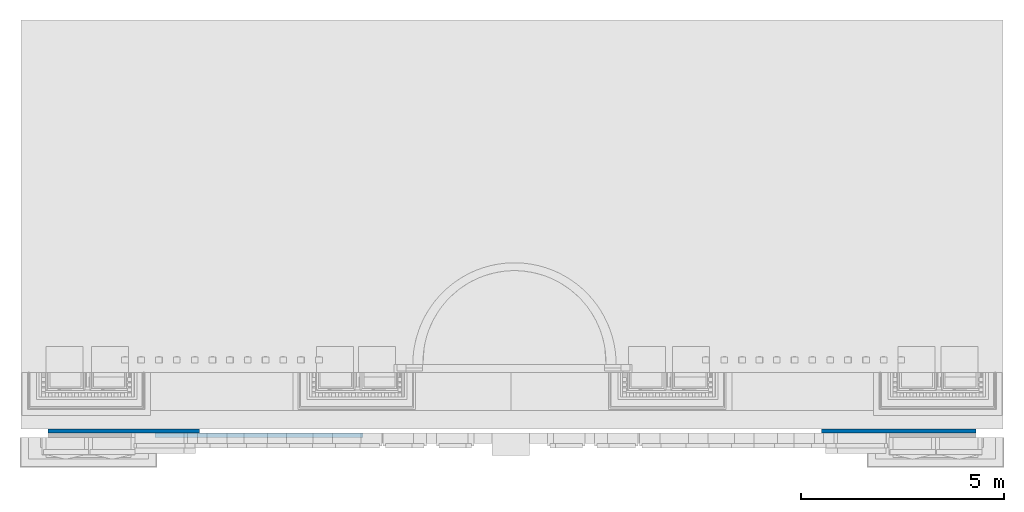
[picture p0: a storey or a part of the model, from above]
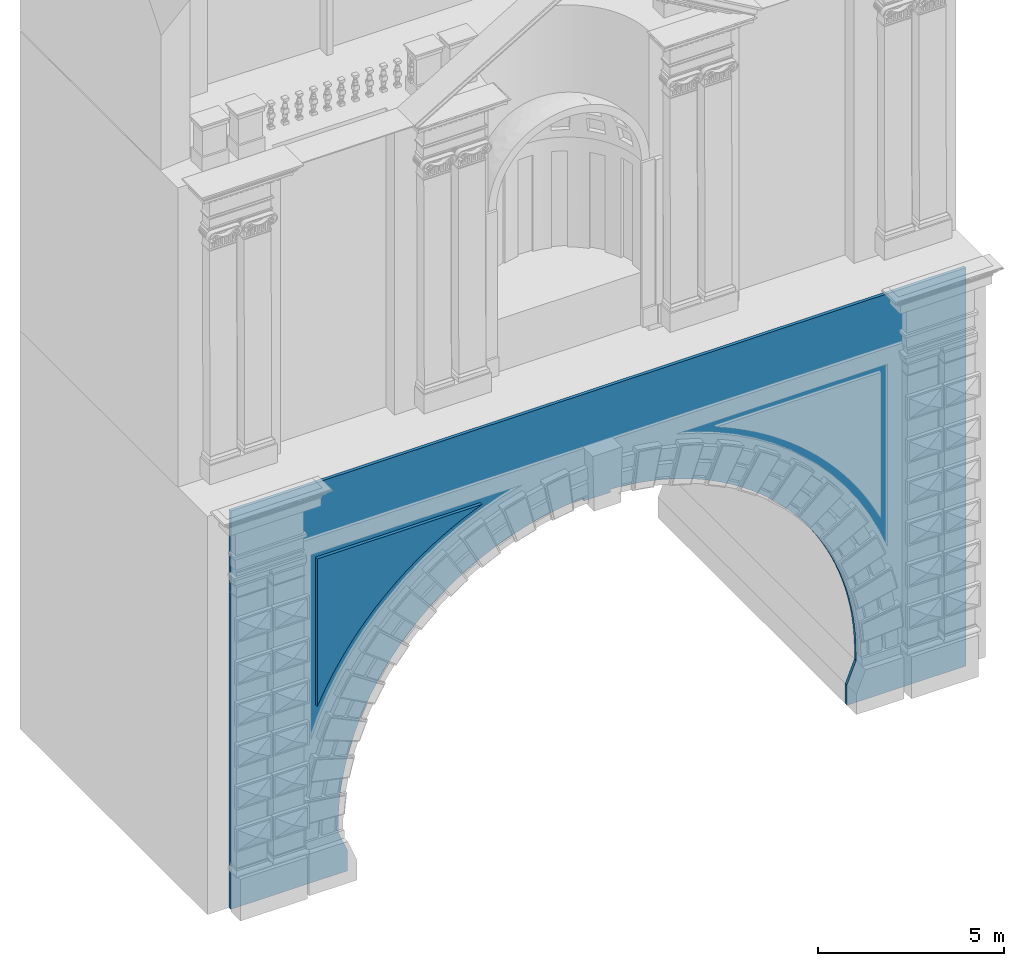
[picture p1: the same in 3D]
Properties of the parts of a building model (IFC2X3), part 1 of 2

# File
Description: ViewDefinition [CoordinationView_V2.0, QuantityTakeOffAddOnView]
File name: 0001
Time: 2019-05-15T13:14:59
Written by: The EXPRESS Data Manager Version 5.02.0100.07 : 28 Aug 2013
Made in: 20190108_1515(x64) - Exporter 19.2.1.1 - Alternate UI 19.2.1.1
Comment: STEP Physical File produced by: The EXPRESS Data Manager Version 5.02.0100.07 : 28 Aug 2013 * Module: EDMstepFileFactory/EDMstandAlone * Creation date: Wed May 15 13:14:59 2019 * Host: Angelo * Database: C:\Users\angel\AppData\Local\Temp\{2247383F-8AE9-40DE-8C0D-A3E6B9A9C0B3}\ifc * Database version: 5507 * Database creation date: Wed May 15 13:14:50 2019 * Schema: IFC2X3 * Model: DataRepository.ifc * Model creation date: Wed May 15 13:14:51 2019 * Header model: DataRepository.ifc_HeaderModel * Header model creation date: Wed May 15 13:14:51 2019 * EDMuser: sdai-user * EDMgroup: sdai-group * License ID and type: 5605 : Permanent license. Expiry date: * EDMstepFileFactory options: 020000

# IfcProject, 0001
LongName: Nome; Phase: Stato

# IfcSite, Default
RefLatitude: 41, 47, 59, 997253; RefLongitude: 12, 36, 0, 1373; RefElevation: 0 m
Altro - Categoria: Informazioni sul progetto; Data di consegna del progetto: Data; Indirizzo del progetto: Immettere l'indirizzo; Nome del cliente: Proprietario; Nome del progetto: Nome; Numero del progetto: 0001; Stato del progetto: Stato

# IfcBuilding
Pset_BuildingCommon - NumberOfStoreys: 3
Altro - Categoria: Informazioni sul progetto; Data di consegna del progetto: Data; Indirizzo del progetto: Immettere l'indirizzo; Nome del cliente: Proprietario; Nome del progetto: Nome; Numero del progetto: 0001; Stato del progetto: Stato

# IfcBuildingStorey (3)
Vincoli(Type) - Base quota altimetrica: Punto base progetto
Grafica(Type) - Colore: 0; Modello di linea: Centro; Simbolo: Estremità del livello - Cerchio: Estremità del livello - Cerchio; Simbolo a estremità 1 per default: no; Simbolo a estremità 2 per default: yes; Spessore di linea: 1
Dati identità(Type) - Nome del tipo: Estremità 8 mm
Altro(Type) - Categoria: Livelli; Nome famiglia: Livello
Altro - Categoria: Livelli; Famiglia: Livello: Estremità 8 mm; Famiglia e tipo: Livello: Estremità 8 mm; ID tipo: Livello: Estremità 8 mm; Tipo: Livello: Estremità 8 mm
Dati identità - Strutturale: no; Piano edificio: yes
Dimensioni - Altezza di calcolo: 0 m
Name | LongName = Nome | Elevation (m) = Quota altimetrica (m)
Livello 1 | Livello 1 | 0
Livello 2 | Livello 2 | 13.3668
Livello 3 | Livello 3 | 23.3294

# IfcBuildingElementProxy (414)
Pset_BuildingElementProxyCommon - Reference: Stratigrafia
Altro - Categoria: Stratigrafia
Dati - ESE_RI: 00
Dati identità - Mostra punti di manipolazione: no; Categoria originale: Modelli generici
Dimensioni - Esclusione: no; La forma è stata modificata: no
Fasi - Fase creata da originale: yes; Fase demolita da originale: yes; Fase di creazione: Fase 1
Name (Stratigrafia:...) | In | Material = Materiale | ESE_AR = ESE_RI_D = ESE_RI_M | Materiale in base a originale | Famiglia originale | Tipo originale | Volume (m3) | Livello di base
223069 | Livello 1 | Piperno | 01 | yes | Parasta_Piano terra | Parasta bugnata | 1.42777 | Livello: Livello 1
223070 | Livello 1 | Travertino | 01 | yes | Parasta_Piano terra | Parasta bugnata | 0.0227881 | Livello: Livello 1
223071 | Livello 1 | Travertino | 01 | yes | Parasta_Piano terra | Parasta bugnata | 2.51151 | Livello: Livello 1
223072 | Livello 1 | Piperno | 01 | yes | Parasta_Piano terra | Parasta bugnata | 0.101188 | Livello: Livello 1
223073 | Livello 1 | Piperno | 01 | yes | Parasta_Piano terra | Parasta bugnata | 0.101188 | Livello: Livello 1
223074 | Livello 1 | Piperno | 01 | yes | Parasta_Piano terra | Parasta bugnata | 0.101188 | Livello: Livello 1
223075 | Livello 1 | Piperno | 01 | yes | Parasta_Piano terra | Parasta bugnata | 0.101188 | Livello: Livello 1
223076 | Livello 1 | Piperno | 01 | yes | Parasta_Piano terra | Parasta bugnata | 0.101188 | Livello: Livello 1
223077 | Livello 1 | Piperno | 01 | yes | Parasta_Piano terra | Parasta bugnata | 0.101188 | Livello: Livello 1
223078 | Livello 1 | Travertino | 01 | yes | Parasta_Piano terra | Parasta bugnata | 0.0072461 | Livello: Livello 1
223079 | Livello 1 | Travertino | 01 | yes | Parasta_Piano terra | Parasta bugnata | 0.0966768 | Livello: Livello 1
223080 | Livello 1 | Travertino | 01 | yes | Parasta_Piano terra | Parasta bugnata | 0.02099 | Livello: Livello 1
223081 | Livello 1 | Travertino | 01 | yes | Parasta_Piano terra | Parasta bugnata | 0.0523646 | Livello: Livello 1
223082 | Livello 1 | Travertino | 01 | yes | Parasta_Piano terra | Parasta bugnata | 0.0608989 | Livello: Livello 1
223083 | Livello 1 | Travertino | 01 | yes | Parasta_Piano terra | Parasta bugnata | 0.0227881 | Livello: Livello 1
223084 | Livello 1 | Travertino | 01 | yes | Parasta_Piano terra | Parasta bugnata | 2.51151 | Livello: Livello 1
223085 | Livello 1 | Piperno | 01 | yes | Parasta_Piano terra | Parasta bugnata | 0.101188 | Livello: Livello 1
223086 | Livello 1 | Piperno | 01 | yes | Parasta_Piano terra | Parasta bugnata | 0.101188 | Livello: Livello 1
223087 | Livello 1 | Piperno | 01 | yes | Parasta_Piano terra | Parasta bugnata | 0.101188 | Livello: Livello 1
223088 | Livello 1 | Piperno | 01 | yes | Parasta_Piano terra | Parasta bugnata | 0.101188 | Livello: Livello 1
223089 | Livello 1 | Piperno | 01 | yes | Parasta_Piano terra | Parasta bugnata | 0.101188 | Livello: Livello 1
223090 | Livello 1 | Piperno | 01 | yes | Parasta_Piano terra | Parasta bugnata | 0.101188 | Livello: Livello 1
223091 | Livello 1 | Travertino | 01 | yes | Parasta_Piano terra | Parasta bugnata | 0.0072461 | Livello: Livello 1
223092 | Livello 1 | Travertino | 01 | yes | Parasta_Piano terra | Parasta bugnata | 0.0966768 | Livello: Livello 1
223093 | Livello 1 | Travertino | 01 | yes | Parasta_Piano terra | Parasta bugnata | 0.02099 | Livello: Livello 1
223094 | Livello 1 | Travertino | 01 | yes | Parasta_Piano terra | Parasta bugnata | 0.0523646 | Livello: Livello 1
223095 | Livello 1 | Travertino | 01 | yes | Parasta_Piano terra | Parasta bugnata | 0.0829303 | Livello: Livello 1
223096 | Livello 1 | Travertino | 01 | yes | Parasta_Piano terra | Parasta bugnata | 0.0317666 | Livello: Livello 1
223097 | Livello 1 | Piperno | 01 | yes | Parasta_Piano terra | Parasta bugnata | 0.207453 | Livello: Livello 1
223098 | Livello 1 | Piperno | 01 | yes | Parasta_Piano terra | Parasta bugnata | 0.0674188 | Livello: Livello 1
223099 | Livello 1 | Travertino | 01 | yes | Parasta_Piano terra | Parasta bugnata | 0.5069 | Livello: Livello 1
223100 | Livello 1 | Travertino | 01 | yes | Parasta_Piano terra | Parasta bugnata | 0.0573057 | Livello: Livello 1
223101 | Livello 1 | Travertino | 01 | yes | Parasta_Piano terra | Parasta bugnata | 0.026402 | Livello: Livello 1
223102 | Livello 1 | Travertino | 01 | yes | Parasta_Piano terra | Parasta bugnata | 0.0573057 | Livello: Livello 1
223103 | Livello 1 | Travertino | 01 | yes | Parasta_Piano terra | Parasta bugnata | 0.026402 | Livello: Livello 1
223104 | Livello 1 | Piperno | 01 | yes | Parasta_Piano terra | Parasta bugnata | 0.0268056 | Livello: Livello 1
223105 | Livello 1 | Piperno | 01 | yes | Parasta_Piano terra | Parasta bugnata | 0.0268056 | Livello: Livello 1
223106 | Livello 1 | Piperno | 01 | yes | Parasta_Piano terra | Parasta bugnata | 0.0268056 | Livello: Livello 1
223107 | Livello 1 | Piperno | 01 | yes | Parasta_Piano terra | Parasta bugnata | 0.0268056 | Livello: Livello 1
223108 | Livello 1 | Piperno | 01 | yes | Parasta_Piano terra | Parasta bugnata | 0.0268056 | Livello: Livello 1
223109 | Livello 1 | Piperno | 01 | yes | Parasta_Piano terra | Parasta bugnata | 0.0268056 | Livello: Livello 1
223110 | Livello 1 | Piperno | 01 | yes | Parasta_Piano terra | Parasta bugnata | 0.0268056 | Livello: Livello 1
223111 | Livello 1 | Piperno | 01 | yes | Parasta_Piano terra | Parasta bugnata | 0.0268056 | Livello: Livello 1
223112 | Livello 1 | Piperno | 01 | yes | Parasta_Piano terra | Parasta bugnata | 0.0268056 | Livello: Livello 1
223113 | Livello 1 | Piperno | 01 | yes | Parasta_Piano terra | Parasta bugnata | 0.0268056 | Livello: Livello 1
223114 | Livello 1 | Piperno | 01 | yes | Parasta_Piano terra | Parasta bugnata | 0.0268056 | Livello: Livello 1
223115 | Livello 1 | Piperno | 01 | yes | Parasta_Piano terra | Parasta bugnata | 0.0268056 | Livello: Livello 1
223116 | Livello 1 | Piperno | 01 | yes | Parasta_Piano terra | Parasta bugnata | 0.431277 | Livello: Livello 1
223117 | Livello 1 | Piperno | 01 | yes | Parasta_Piano terra | Parasta bugnata | 0.0748414 | Livello: Livello 1
223118 | Livello 1 | Piperno | 01 | yes | Parasta_Piano terra | Parasta bugnata | 0.132494 | Livello: Livello 1
223119 | Livello 1 | Piperno | 01 | yes | Parasta_Piano terra | Parasta bugnata | 0.369268 | Livello: Livello 1
223129 | Livello 1 | Travertino | 01 | yes | Arco Ingresso_Fronte Arcoleo | Arco ingresso bugnato | 3.44359 | Livello: Livello 1
223130 | Livello 1 | Piperno | 01 | yes | Arco Ingresso_Fronte Arcoleo | Arco ingresso bugnato | 0.303287 | Livello: Livello 1
223131 | Livello 1 | Piperno | 01 | yes | Arco Ingresso_Fronte Arcoleo | Arco ingresso bugnato | 0.083023 | Livello: Livello 1
223132 | Livello 1 | Piperno | 01 | yes | Arco Ingresso_Fronte Arcoleo | Arco ingresso bugnato | 0.303287 | Livello: Livello 1
223133 | Livello 1 | Piperno | 01 | yes | Arco Ingresso_Fronte Arcoleo | Arco ingresso bugnato | 0.083023 | Livello: Livello 1
223134 | Livello 1 | Piperno | 01 | yes | Arco Ingresso_Fronte Arcoleo | Arco ingresso bugnato | 0.303287 | Livello: Livello 1
223135 | Livello 1 | Piperno | 01 | yes | Arco Ingresso_Fronte Arcoleo | Arco ingresso bugnato | 0.083023 | Livello: Livello 1
223136 | Livello 1 | Piperno | 01 | yes | Arco Ingresso_Fronte Arcoleo | Arco ingresso bugnato | 0.303287 | Livello: Livello 1
223137 | Livello 1 | Piperno | 01 | yes | Arco Ingresso_Fronte Arcoleo | Arco ingresso bugnato | 0.083023 | Livello: Livello 1
223138 | Livello 1 | Piperno | 01 | yes | Arco Ingresso_Fronte Arcoleo | Arco ingresso bugnato | 0.303287 | Livello: Livello 1
223139 | Livello 1 | Piperno | 01 | yes | Arco Ingresso_Fronte Arcoleo | Arco ingresso bugnato | 0.083023 | Livello: Livello 1
223140 | Livello 1 | Piperno | 01 | yes | Arco Ingresso_Fronte Arcoleo | Arco ingresso bugnato | 0.303287 | Livello: Livello 1
223141 | Livello 1 | Piperno | 01 | yes | Arco Ingresso_Fronte Arcoleo | Arco ingresso bugnato | 0.083023 | Livello: Livello 1
223142 | Livello 1 | Piperno | 01 | yes | Arco Ingresso_Fronte Arcoleo | Arco ingresso bugnato | 0.303287 | Livello: Livello 1
223143 | Livello 1 | Piperno | 01 | yes | Arco Ingresso_Fronte Arcoleo | Arco ingresso bugnato | 0.083023 | Livello: Livello 1
223144 | Livello 1 | Piperno | 01 | yes | Arco Ingresso_Fronte Arcoleo | Arco ingresso bugnato | 0.303287 | Livello: Livello 1
223145 | Livello 1 | Piperno | 01 | yes | Arco Ingresso_Fronte Arcoleo | Arco ingresso bugnato | 0.083023 | Livello: Livello 1
223146 | Livello 1 | Piperno | 01 | yes | Arco Ingresso_Fronte Arcoleo | Arco ingresso bugnato | 0.303287 | Livello: Livello 1
223147 | Livello 1 | Piperno | 01 | yes | Arco Ingresso_Fronte Arcoleo | Arco ingresso bugnato | 0.083023 | Livello: Livello 1
223148 | Livello 1 | Piperno | 01 | yes | Arco Ingresso_Fronte Arcoleo | Arco ingresso bugnato | 0.303287 | Livello: Livello 1
223149 | Livello 1 | Piperno | 01 | yes | Arco Ingresso_Fronte Arcoleo | Arco ingresso bugnato | 0.083023 | Livello: Livello 1
223150 | Livello 1 | Piperno | 01 | yes | Arco Ingresso_Fronte Arcoleo | Arco ingresso bugnato | 0.866418 | Livello: Livello 1
223151 | Livello 1 | Piperno | 01 | yes | Arco Ingresso_Fronte Arcoleo | Arco ingresso bugnato | 0.303287 | Livello: Livello 1
223152 | Livello 1 | Piperno | 01 | yes | Arco Ingresso_Fronte Arcoleo | Arco ingresso bugnato | 0.083023 | Livello: Livello 1
223153 | Livello 1 | Piperno | 01 | yes | Arco Ingresso_Fronte Arcoleo | Arco ingresso bugnato | 0.303287 | Livello: Livello 1
223154 | Livello 1 | Piperno | 01 | yes | Arco Ingresso_Fronte Arcoleo | Arco ingresso bugnato | 0.083023 | Livello: Livello 1
223155 | Livello 1 | Piperno | 01 | yes | Arco Ingresso_Fronte Arcoleo | Arco ingresso bugnato | 0.303287 | Livello: Livello 1
223156 | Livello 1 | Piperno | 01 | yes | Arco Ingresso_Fronte Arcoleo | Arco ingresso bugnato | 0.083023 | Livello: Livello 1
223157 | Livello 1 | Piperno | 01 | yes | Arco Ingresso_Fronte Arcoleo | Arco ingresso bugnato | 0.303287 | Livello: Livello 1
223158 | Livello 1 | Piperno | 01 | yes | Arco Ingresso_Fronte Arcoleo | Arco ingresso bugnato | 0.083023 | Livello: Livello 1
223159 | Livello 1 | Piperno | 01 | yes | Arco Ingresso_Fronte Arcoleo | Arco ingresso bugnato | 0.303287 | Livello: Livello 1
223160 | Livello 1 | Piperno | 01 | yes | Arco Ingresso_Fronte Arcoleo | Arco ingresso bugnato | 0.083023 | Livello: Livello 1
223161 | Livello 1 | Piperno | 01 | yes | Arco Ingresso_Fronte Arcoleo | Arco ingresso bugnato | 0.303287 | Livello: Livello 1
223162 | Livello 1 | Piperno | 01 | yes | Arco Ingresso_Fronte Arcoleo | Arco ingresso bugnato | 0.083023 | Livello: Livello 1
223163 | Livello 1 | Piperno | 01 | yes | Arco Ingresso_Fronte Arcoleo | Arco ingresso bugnato | 0.303287 | Livello: Livello 1
223164 | Livello 1 | Piperno | 01 | yes | Arco Ingresso_Fronte Arcoleo | Arco ingresso bugnato | 0.083023 | Livello: Livello 1
223165 | Livello 1 | Piperno | 01 | yes | Arco Ingresso_Fronte Arcoleo | Arco ingresso bugnato | 0.303287 | Livello: Livello 1
223166 | Livello 1 | Piperno | 01 | yes | Arco Ingresso_Fronte Arcoleo | Arco ingresso bugnato | 0.083023 | Livello: Livello 1
223167 | Livello 1 | Piperno | 01 | yes | Arco Ingresso_Fronte Arcoleo | Arco ingresso bugnato | 0.303287 | Livello: Livello 1
223168 | Livello 1 | Piperno | 01 | yes | Arco Ingresso_Fronte Arcoleo | Arco ingresso bugnato | 0.083023 | Livello: Livello 1
223169 | Livello 1 | Piperno | 01 | yes | Arco Ingresso_Fronte Arcoleo | Arco ingresso bugnato | 0.303287 | Livello: Livello 1
223170 | Livello 1 | Piperno | 01 | yes | Arco Ingresso_Fronte Arcoleo | Arco ingresso bugnato | 0.083023 | Livello: Livello 1
223171 | Livello 1 | Travertino | 01 | yes | Arco Ingresso_Fronte Arcoleo | Arco ingresso bugnato | 3.44358 | Livello: Livello 1
223172 | Livello 1 | Piperno | 01 | yes | Arco Ingresso_Fronte Arcoleo | Arco ingresso bugnato | 0.963143 | Livello: Livello 1
223173 | Livello 1 | Travertino | 01 | yes | Arco Ingresso_Fronte Arcoleo | Arco ingresso bugnato | 0.102829 | Livello: Livello 1
223174 | Livello 1 | Piperno | 01 | yes | Arco Ingresso_Fronte Arcoleo | Arco ingresso bugnato | 0.963143 | Livello: Livello 1
223175 | Livello 1 | Travertino | 01 | yes | Arco Ingresso_Fronte Arcoleo | Arco ingresso bugnato | 0.102829 | Livello: Livello 1
223188 | Livello 1 | Piperno | 01 | yes | Parasta_Piano terra | Parasta bugnata | 1.42777 | Livello: Livello 1
223189 | Livello 1 | Travertino | 01 | yes | Parasta_Piano terra | Parasta bugnata | 0.0227881 | Livello: Livello 1
223190 | Livello 1 | Travertino | 01 | yes | Parasta_Piano terra | Parasta bugnata | 2.51151 | Livello: Livello 1
223191 | Livello 1 | Piperno | 01 | yes | Parasta_Piano terra | Parasta bugnata | 0.101188 | Livello: Livello 1
223192 | Livello 1 | Piperno | 01 | yes | Parasta_Piano terra | Parasta bugnata | 0.101188 | Livello: Livello 1
223193 | Livello 1 | Piperno | 01 | yes | Parasta_Piano terra | Parasta bugnata | 0.101188 | Livello: Livello 1
223194 | Livello 1 | Piperno | 01 | yes | Parasta_Piano terra | Parasta bugnata | 0.101188 | Livello: Livello 1
223195 | Livello 1 | Piperno | 01 | yes | Parasta_Piano terra | Parasta bugnata | 0.101188 | Livello: Livello 1
223196 | Livello 1 | Piperno | 01 | yes | Parasta_Piano terra | Parasta bugnata | 0.101188 | Livello: Livello 1
223197 | Livello 1 | Travertino | 01 | yes | Parasta_Piano terra | Parasta bugnata | 0.0072461 | Livello: Livello 1
223198 | Livello 1 | Travertino | 01 | yes | Parasta_Piano terra | Parasta bugnata | 0.0966768 | Livello: Livello 1
223199 | Livello 1 | Travertino | 01 | yes | Parasta_Piano terra | Parasta bugnata | 0.02099 | Livello: Livello 1
223200 | Livello 1 | Travertino | 01 | yes | Parasta_Piano terra | Parasta bugnata | 0.0523646 | Livello: Livello 1
223201 | Livello 1 | Travertino | 01 | yes | Parasta_Piano terra | Parasta bugnata | 0.0608989 | Livello: Livello 1
223202 | Livello 1 | Travertino | 01 | yes | Parasta_Piano terra | Parasta bugnata | 0.0227881 | Livello: Livello 1
223203 | Livello 1 | Travertino | 01 | yes | Parasta_Piano terra | Parasta bugnata | 2.51151 | Livello: Livello 1
223204 | Livello 1 | Piperno | 01 | yes | Parasta_Piano terra | Parasta bugnata | 0.101188 | Livello: Livello 1
223205 | Livello 1 | Piperno | 01 | yes | Parasta_Piano terra | Parasta bugnata | 0.101188 | Livello: Livello 1
223206 | Livello 1 | Piperno | 01 | yes | Parasta_Piano terra | Parasta bugnata | 0.101188 | Livello: Livello 1
223207 | Livello 1 | Piperno | 01 | yes | Parasta_Piano terra | Parasta bugnata | 0.101188 | Livello: Livello 1
223208 | Livello 1 | Piperno | 01 | yes | Parasta_Piano terra | Parasta bugnata | 0.101188 | Livello: Livello 1
223209 | Livello 1 | Piperno | 01 | yes | Parasta_Piano terra | Parasta bugnata | 0.101188 | Livello: Livello 1
223210 | Livello 1 | Travertino | 01 | yes | Parasta_Piano terra | Parasta bugnata | 0.0072461 | Livello: Livello 1
223211 | Livello 1 | Travertino | 01 | yes | Parasta_Piano terra | Parasta bugnata | 0.0966768 | Livello: Livello 1
223212 | Livello 1 | Travertino | 01 | yes | Parasta_Piano terra | Parasta bugnata | 0.02099 | Livello: Livello 1
223213 | Livello 1 | Travertino | 01 | yes | Parasta_Piano terra | Parasta bugnata | 0.0523646 | Livello: Livello 1
223214 | Livello 1 | Travertino | 01 | yes | Parasta_Piano terra | Parasta bugnata | 0.0829303 | Livello: Livello 1
223215 | Livello 1 | Travertino | 01 | yes | Parasta_Piano terra | Parasta bugnata | 0.0317666 | Livello: Livello 1
223216 | Livello 1 | Piperno | 01 | yes | Parasta_Piano terra | Parasta bugnata | 0.207453 | Livello: Livello 1
223217 | Livello 1 | Piperno | 01 | yes | Parasta_Piano terra | Parasta bugnata | 0.0674188 | Livello: Livello 1
223218 | Livello 1 | Travertino | 01 | yes | Parasta_Piano terra | Parasta bugnata | 0.5069 | Livello: Livello 1
223219 | Livello 1 | Travertino | 01 | yes | Parasta_Piano terra | Parasta bugnata | 0.0573057 | Livello: Livello 1
223220 | Livello 1 | Travertino | 01 | yes | Parasta_Piano terra | Parasta bugnata | 0.026402 | Livello: Livello 1
223221 | Livello 1 | Travertino | 01 | yes | Parasta_Piano terra | Parasta bugnata | 0.0573057 | Livello: Livello 1
223222 | Livello 1 | Travertino | 01 | yes | Parasta_Piano terra | Parasta bugnata | 0.026402 | Livello: Livello 1
223223 | Livello 1 | Piperno | 01 | yes | Parasta_Piano terra | Parasta bugnata | 0.0268056 | Livello: Livello 1
223224 | Livello 1 | Piperno | 01 | yes | Parasta_Piano terra | Parasta bugnata | 0.0268056 | Livello: Livello 1
223225 | Livello 1 | Piperno | 01 | yes | Parasta_Piano terra | Parasta bugnata | 0.0268056 | Livello: Livello 1
223226 | Livello 1 | Piperno | 01 | yes | Parasta_Piano terra | Parasta bugnata | 0.0268056 | Livello: Livello 1
223227 | Livello 1 | Piperno | 01 | yes | Parasta_Piano terra | Parasta bugnata | 0.0268056 | Livello: Livello 1
223228 | Livello 1 | Piperno | 01 | yes | Parasta_Piano terra | Parasta bugnata | 0.0268056 | Livello: Livello 1
223229 | Livello 1 | Piperno | 01 | yes | Parasta_Piano terra | Parasta bugnata | 0.0268056 | Livello: Livello 1
223230 | Livello 1 | Piperno | 01 | yes | Parasta_Piano terra | Parasta bugnata | 0.0268056 | Livello: Livello 1
223231 | Livello 1 | Piperno | 01 | yes | Parasta_Piano terra | Parasta bugnata | 0.0268056 | Livello: Livello 1
223232 | Livello 1 | Piperno | 01 | yes | Parasta_Piano terra | Parasta bugnata | 0.0268056 | Livello: Livello 1
223233 | Livello 1 | Piperno | 01 | yes | Parasta_Piano terra | Parasta bugnata | 0.0268056 | Livello: Livello 1
223234 | Livello 1 | Piperno | 01 | yes | Parasta_Piano terra | Parasta bugnata | 0.0268056 | Livello: Livello 1
223235 | Livello 1 | Piperno | 01 | yes | Parasta_Piano terra | Parasta bugnata | 0.431277 | Livello: Livello 1
223236 | Livello 1 | Piperno | 01 | yes | Parasta_Piano terra | Parasta bugnata | 0.0748414 | Livello: Livello 1
223237 | Livello 1 | Piperno | 01 | yes | Parasta_Piano terra | Parasta bugnata | 0.132494 | Livello: Livello 1
223238 | Livello 1 | Piperno | 01 | yes | Parasta_Piano terra | Parasta bugnata | 0.369268 | Livello: Livello 1
223248 | Livello 2 | Intonaco Liscio | 02 | yes | Nicchia Laterale | Nicchia Laterale | 5.30265 | Livello: Livello 2
223249 | Livello 2 | Piperno | 02 | yes | Nicchia Laterale | Nicchia Laterale | 0.838648 | Livello: Livello 2
223250 | Livello 2 | Travertino | 02 | yes | Nicchia Laterale | Nicchia Laterale | 0.519399 | Livello: Livello 2
223251 | Livello 2 | Travertino | 02 | no | Nicchia Laterale | Nicchia Laterale | 0.183577 | Livello: Livello 2
223252 | Livello 2 | Travertino | 02 | no | Nicchia Laterale | Nicchia Laterale | 0.0514958 | Livello: Livello 2
223253 | Livello 2 | Travertino | 02 | no | Nicchia Laterale | Nicchia Laterale | 0.065907 | Livello: Livello 2
223254 | Livello 2 | Travertino | 02 | no | Nicchia Laterale | Nicchia Laterale | 0.0524481 | Livello: Livello 2
223255 | Livello 2 | Travertino | 02 | no | Nicchia Laterale | Nicchia Laterale | 0.188709 | Livello: Livello 2
223256 | Livello 2 |  | 02 | yes | Nicchia Laterale | Nicchia Laterale | 0.978936 | Livello: Livello 2
223257 | Livello 2 | Travertino | 02 | yes | Nicchia Laterale | Nicchia Laterale | 0.102934 | Livello: Livello 2
223258 | Livello 2 | Travertino | 02 | yes | Nicchia Laterale | Nicchia Laterale | 0.190451 | Livello: Livello 2
223259 | Livello 2 | Travertino | 02 | yes | Nicchia Laterale | Nicchia Laterale | 0.170767 | Livello: Livello 2
223260 | Livello 2 | Travertino | 02 | yes | Nicchia Laterale | Nicchia Laterale | 0.102934 | Livello: Livello 2
223261 | Livello 2 | Travertino | 02 | yes | Nicchia Laterale | Nicchia Laterale | 0.190451 | Livello: Livello 2
223262 | Livello 2 | Travertino | 02 | yes | Nicchia Laterale | Nicchia Laterale | 0.170767 | Livello: Livello 2
223263 | Livello 2 | Intonaco Liscio | 02 | yes | Nicchia Laterale | Nicchia Laterale | 0.0603934 | Livello: Livello 2
223273 | Livello 1 | Travertino | 02 | yes | Nicchia centrale | Nicchia centrale | 3.82044 | Livello: Livello 1
223274 | Livello 1 | Travertino | 02 | yes | Nicchia centrale | Nicchia centrale | 0.158421 | Livello: Livello 1
223275 | Livello 1 | Travertino | 02 | yes | Nicchia centrale | Nicchia centrale | 0.159166 | Livello: Livello 1
223276 | Livello 1 | Travertino | 02 | yes | Nicchia centrale | Nicchia centrale | 0.158421 | Livello: Livello 1
223277 | Livello 1 | Travertino | 02 | yes | Nicchia centrale | Nicchia centrale | 0.159166 | Livello: Livello 1
223279 | Livello 1 | Travertino | 02 | yes | Nicchia centrale | Nicchia centrale | 6.73469 | Livello: Livello 1
223280 | Livello 1 | Intonaco Liscio | 02 | yes | Nicchia centrale | Nicchia centrale | 16.9 | Livello: Livello 1
223281 | Livello 1 | Travertino | 02 | yes | Nicchia centrale | Nicchia centrale | 0.0365358 | Livello: Livello 1
223282 | Livello 1 | Travertino | 02 | yes | Nicchia centrale | Nicchia centrale | 0.0352073 | Livello: Livello 1
223283 | Livello 1 | Travertino | 02 | yes | Nicchia centrale | Nicchia centrale | 0.0410155 | Livello: Livello 1
223284 | Livello 1 | Travertino | 02 | yes | Nicchia centrale | Nicchia centrale | 0.0258276 | Livello: Livello 1
223294 | Livello 2 | Intonaco Liscio | 02 | yes | Nicchia Laterale | Nicchia Laterale | 5.30265 | Livello: Livello 2
223295 | Livello 2 | Piperno | 02 | yes | Nicchia Laterale | Nicchia Laterale | 0.838648 | Livello: Livello 2
223296 | Livello 2 | Travertino | 02 | yes | Nicchia Laterale | Nicchia Laterale | 0.519399 | Livello: Livello 2
223297 | Livello 2 | Travertino | 02 | no | Nicchia Laterale | Nicchia Laterale | 0.183577 | Livello: Livello 2
223298 | Livello 2 | Travertino | 02 | no | Nicchia Laterale | Nicchia Laterale | 0.0514958 | Livello: Livello 2
223299 | Livello 2 | Travertino | 02 | no | Nicchia Laterale | Nicchia Laterale | 0.065907 | Livello: Livello 2
223300 | Livello 2 | Travertino | 02 | no | Nicchia Laterale | Nicchia Laterale | 0.0524481 | Livello: Livello 2
223301 | Livello 2 | Travertino | 02 | no | Nicchia Laterale | Nicchia Laterale | 0.188709 | Livello: Livello 2
223302 | Livello 2 |  | 02 | yes | Nicchia Laterale | Nicchia Laterale | 0.978936 | Livello: Livello 2
223303 | Livello 2 | Travertino | 02 | yes | Nicchia Laterale | Nicchia Laterale | 0.102934 | Livello: Livello 2
223304 | Livello 2 | Travertino | 02 | yes | Nicchia Laterale | Nicchia Laterale | 0.190451 | Livello: Livello 2
223305 | Livello 2 | Travertino | 02 | yes | Nicchia Laterale | Nicchia Laterale | 0.170767 | Livello: Livello 2
223306 | Livello 2 | Travertino | 02 | yes | Nicchia Laterale | Nicchia Laterale | 0.102934 | Livello: Livello 2
223307 | Livello 2 | Travertino | 02 | yes | Nicchia Laterale | Nicchia Laterale | 0.190451 | Livello: Livello 2
223308 | Livello 2 | Travertino | 02 | yes | Nicchia Laterale | Nicchia Laterale | 0.170767 | Livello: Livello 2
223309 | Livello 2 | Intonaco Liscio | 02 | yes | Nicchia Laterale | Nicchia Laterale | 0.0603934 | Livello: Livello 2
223386 | Livello 1 |  | 02 | yes | Parasta_Piano Primo 2 | Parasta Liscia_centrale | 0.00746349 | Livello: Livello 1
223387 | Livello 1 |  | 02 | yes | Parasta_Piano Primo 2 | Parasta Liscia_centrale | 0.0176679 | Livello: Livello 1
223388 | Livello 1 | Travertino | 02 | yes | Parasta_Piano Primo 2 | Parasta Liscia_centrale | 0.101618 | Livello: Livello 1
223391 | Livello 1 | Piperno | 02 | yes | Parasta_Piano Primo 2 | Parasta Liscia_centrale | 0.653767 | Livello: Livello 1
223392 | Livello 1 | Piperno | 02 | yes | Parasta_Piano Primo 2 | Parasta Liscia_centrale | 0.0556768 | Livello: Livello 1
223394 | Livello 1 | Piperno | 02 | yes | Parasta_Piano Primo 2 | Parasta Liscia_centrale | 2.15049 | Livello: Livello 1
223395 | Livello 1 |  | 02 | yes | Parasta_Piano Primo 2 | Parasta Liscia_centrale | 0.00746349 | Livello: Livello 1
223398 | Livello 1 |  | 02 | yes | Parasta_Piano Primo 2 | Parasta Liscia_centrale | 0.0176679 | Livello: Livello 1
223399 | Livello 1 | Travertino | 02 | yes | Parasta_Piano Primo 2 | Parasta Liscia_centrale | 0.101618 | Livello: Livello 1
223400 | Livello 1 | Travertino | 02 | yes | Parasta_Piano Primo 2 | Parasta Liscia_centrale | 0.066141 | Livello: Livello 1
223401 | Livello 1 | Travertino | 02 | yes | Parasta_Piano Primo 2 | Parasta Liscia_centrale | 0.108814 | Livello: Livello 1
223402 | Livello 1 | Travertino | 02 | yes | Parasta_Piano Primo 2 | Parasta Liscia_centrale | 0.0661334 | Livello: Livello 1
223403 | Livello 1 | Travertino | 02 | yes | Parasta_Piano Primo 2 | Parasta Liscia_centrale | 0.108807 | Livello: Livello 1
223448 | Livello 1 |  | 02 | yes | Parasta_Piano Primo 2 | Parasta Liscia_centrale | 0.00746349 | Livello: Livello 1
223449 | Livello 1 |  | 02 | yes | Parasta_Piano Primo 2 | Parasta Liscia_centrale | 0.0176679 | Livello: Livello 1
223450 | Livello 1 | Travertino | 02 | yes | Parasta_Piano Primo 2 | Parasta Liscia_centrale | 0.101618 | Livello: Livello 1
223453 | Livello 1 | Piperno | 02 | yes | Parasta_Piano Primo 2 | Parasta Liscia_centrale | 0.653767 | Livello: Livello 1
223454 | Livello 1 | Piperno | 02 | yes | Parasta_Piano Primo 2 | Parasta Liscia_centrale | 0.0556768 | Livello: Livello 1
223456 | Livello 1 | Piperno | 02 | yes | Parasta_Piano Primo 2 | Parasta Liscia_centrale | 2.15049 | Livello: Livello 1
223457 | Livello 1 |  | 02 | yes | Parasta_Piano Primo 2 | Parasta Liscia_centrale | 0.00746349 | Livello: Livello 1
223460 | Livello 1 |  | 02 | yes | Parasta_Piano Primo 2 | Parasta Liscia_centrale | 0.0176679 | Livello: Livello 1
223461 | Livello 1 | Travertino | 02 | yes | Parasta_Piano Primo 2 | Parasta Liscia_centrale | 0.101618 | Livello: Livello 1
223462 | Livello 1 | Travertino | 02 | yes | Parasta_Piano Primo 2 | Parasta Liscia_centrale | 0.066141 | Livello: Livello 1
223463 | Livello 1 | Travertino | 02 | yes | Parasta_Piano Primo 2 | Parasta Liscia_centrale | 0.108814 | Livello: Livello 1
223464 | Livello 1 | Travertino | 02 | yes | Parasta_Piano Primo 2 | Parasta Liscia_centrale | 0.0661334 | Livello: Livello 1
223465 | Livello 1 | Travertino | 02 | yes | Parasta_Piano Primo 2 | Parasta Liscia_centrale | 0.108807 | Livello: Livello 1
225919 | Livello 1 |  | 02 | yes | Parasta_Piano Primo 2 | Parasta Liscia_centrale | 0.00594878 | Livello: Livello 1
225920 | Livello 1 |  | 02 | yes | Parasta_Piano Primo 2 | Parasta Liscia_centrale | 0.00807559 | Livello: Livello 1
225921 | Livello 1 |  | 02 | yes | Parasta_Piano Primo 2 | Parasta Liscia_centrale | 0.0108989 | Livello: Livello 1
225922 | Livello 1 |  | 02 | yes | Parasta_Piano Primo 2 | Parasta Liscia_centrale | 0.0119519 | Livello: Livello 1
225923 | Livello 1 |  | 02 | yes | Parasta_Piano Primo 2 | Parasta Liscia_centrale | 0.0161303 | Livello: Livello 1
225924 | Livello 1 | Piperno | 02 | yes | Parasta_Piano Primo 2 | Parasta Liscia_centrale | 0.189326 | Livello: Livello 1
225925 | Livello 1 | Piperno | 02 | yes | Parasta_Piano Primo 2 | Parasta Liscia_centrale | 0.0100946 | Livello: Livello 1
225926 | Livello 1 | Piperno | 02 | yes | Parasta_Piano Primo 2 | Parasta Liscia_centrale | 0.0100946 | Livello: Livello 1
225927 | Livello 1 | Travertino | 02 | yes | Parasta_Piano Primo 2 | Parasta Liscia_centrale | 0.369222 | Livello: Livello 1
225928 | Livello 1 | Piperno | 02 | yes | Parasta_Piano Primo 2 | Parasta Liscia_centrale | 0.017309 | Livello: Livello 1
225929 | Livello 1 | Piperno | 02 | yes | Parasta_Piano Primo 2 | Parasta Liscia_centrale | 0.00282252 | Livello: Livello 1
225930 | Livello 1 | Piperno | 02 | yes | Parasta_Piano Primo 2 | Parasta Liscia_centrale | 0.0891707 | Livello: Livello 1
225931 | Livello 1 | Piperno | 02 | yes | Parasta_Piano Primo 2 | Parasta Liscia_centrale | 0.235123 | Livello: Livello 1
225933 | Livello 1 | Piperno | 02 | yes | Parasta_Piano Primo 2 | Parasta Liscia_centrale | 0.0898849 | Livello: Livello 1
225934 | Livello 1 | Piperno | 02 | yes | Parasta_Piano Primo 2 | Parasta Liscia_centrale | 0.0327858 | Livello: Livello 1
225935 | Livello 1 | Piperno | 02 | yes | Parasta_Piano Primo 2 | Parasta Liscia_centrale | 0.0944687 | Livello: Livello 1
225936 | Livello 1 | Piperno | 02 | yes | Parasta_Piano Primo 2 | Parasta Liscia_centrale | 0.00100709 | Livello: Livello 1
225937 | Livello 1 | Piperno | 02 | yes | Parasta_Piano Primo 2 | Parasta Liscia_centrale | 0.00100709 | Livello: Livello 1
225938 | Livello 1 | Piperno | 02 | yes | Parasta_Piano Primo 2 | Parasta Liscia_centrale | 0.00100709 | Livello: Livello 1
225939 | Livello 1 | Piperno | 02 | yes | Parasta_Piano Primo 2 | Parasta Liscia_centrale | 0.00100709 | Livello: Livello 1
225940 | Livello 1 | Piperno | 02 | yes | Parasta_Piano Primo 2 | Parasta Liscia_centrale | 0.00100709 | Livello: Livello 1
225941 | Livello 1 | Piperno | 02 | yes | Parasta_Piano Primo 2 | Parasta Liscia_centrale | 0.00100709 | Livello: Livello 1
225942 | Livello 1 | Piperno | 02 | yes | Parasta_Piano Primo 2 | Parasta Liscia_centrale | 0.00100709 | Livello: Livello 1
225943 | Livello 1 | Piperno | 02 | yes | Parasta_Piano Primo 2 | Parasta Liscia_centrale | 0.00100709 | Livello: Livello 1
225944 | Livello 1 | Piperno | 02 | yes | Parasta_Piano Primo 2 | Parasta Liscia_centrale | 0.00100709 | Livello: Livello 1
225945 | Livello 1 | Piperno | 02 | yes | Parasta_Piano Primo 2 | Parasta Liscia_centrale | 0.00100709 | Livello: Livello 1
225946 | Livello 1 | Piperno | 02 | yes | Parasta_Piano Primo 2 | Parasta Liscia_centrale | 0.00100709 | Livello: Livello 1
225947 | Livello 1 | Piperno | 02 | yes | Parasta_Piano Primo 2 | Parasta Liscia_centrale | 0.00100709 | Livello: Livello 1
225948 | Livello 1 | Piperno | 02 | yes | Parasta_Piano Primo 2 | Parasta Liscia_centrale | 0.00100709 | Livello: Livello 1
225949 | Livello 1 | Piperno | 02 | yes | Parasta_Piano Primo 2 | Parasta Liscia_centrale | 0.00100709 | Livello: Livello 1
225950 | Livello 1 | Piperno | 02 | yes | Parasta_Piano Primo 2 | Parasta Liscia_centrale | 0.00100709 | Livello: Livello 1
225951 | Livello 1 | Piperno | 02 | yes | Parasta_Piano Primo 2 | Parasta Liscia_centrale | 0.00100709 | Livello: Livello 1
225952 | Livello 1 | Piperno | 02 | yes | Parasta_Piano Primo 2 | Parasta Liscia_centrale | 0.00100709 | Livello: Livello 1
225953 | Livello 1 | Piperno | 02 | yes | Parasta_Piano Primo 2 | Parasta Liscia_centrale | 0.00100709 | Livello: Livello 1
225954 | Livello 1 | Piperno | 02 | yes | Parasta_Piano Primo 2 | Parasta Liscia_centrale | 0.00100709 | Livello: Livello 1
225955 | Livello 1 | Piperno | 02 | yes | Parasta_Piano Primo 2 | Parasta Liscia_centrale | 0.00100709 | Livello: Livello 1
225956 | Livello 1 | Piperno | 02 | yes | Parasta_Piano Primo 2 | Parasta Liscia_centrale | 0.0556768 | Livello: Livello 1
225957 | Livello 1 | Piperno | 02 | yes | Parasta_Piano Primo 2 | Parasta Liscia_centrale | 2.15049 | Livello: Livello 1
225958 | Livello 1 |  | 02 | yes | Parasta_Piano Primo 2 | Parasta Liscia_centrale | 0.00594878 | Livello: Livello 1
225959 | Livello 1 |  | 02 | yes | Parasta_Piano Primo 2 | Parasta Liscia_centrale | 0.00594878 | Livello: Livello 1
225960 | Livello 1 |  | 02 | yes | Parasta_Piano Primo 2 | Parasta Liscia_centrale | 0.00807559 | Livello: Livello 1
225961 | Livello 1 |  | 02 | yes | Parasta_Piano Primo 2 | Parasta Liscia_centrale | 0.0108989 | Livello: Livello 1
225962 | Livello 1 |  | 02 | yes | Parasta_Piano Primo 2 | Parasta Liscia_centrale | 0.0119519 | Livello: Livello 1
225963 | Livello 1 |  | 02 | yes | Parasta_Piano Primo 2 | Parasta Liscia_centrale | 0.0161303 | Livello: Livello 1
225964 | Livello 1 | Piperno | 02 | yes | Parasta_Piano Primo 2 | Parasta Liscia_centrale | 0.189326 | Livello: Livello 1
225965 | Livello 1 | Piperno | 02 | yes | Parasta_Piano Primo 2 | Parasta Liscia_centrale | 0.0100946 | Livello: Livello 1
225966 | Livello 1 | Piperno | 02 | yes | Parasta_Piano Primo 2 | Parasta Liscia_centrale | 0.0100946 | Livello: Livello 1
225967 | Livello 1 | Travertino | 02 | yes | Parasta_Piano Primo 2 | Parasta Liscia_centrale | 0.369222 | Livello: Livello 1
225968 | Livello 1 | Piperno | 02 | yes | Parasta_Piano Primo 2 | Parasta Liscia_centrale | 0.017309 | Livello: Livello 1
225969 | Livello 1 | Piperno | 02 | yes | Parasta_Piano Primo 2 | Parasta Liscia_centrale | 0.00282252 | Livello: Livello 1
225970 | Livello 1 | Piperno | 02 | yes | Parasta_Piano Primo 2 | Parasta Liscia_centrale | 0.0891707 | Livello: Livello 1
225971 | Livello 1 | Piperno | 02 | yes | Parasta_Piano Primo 2 | Parasta Liscia_centrale | 0.235123 | Livello: Livello 1
225973 | Livello 1 | Piperno | 02 | yes | Parasta_Piano Primo 2 | Parasta Liscia_centrale | 0.0898849 | Livello: Livello 1
225974 | Livello 1 | Piperno | 02 | yes | Parasta_Piano Primo 2 | Parasta Liscia_centrale | 0.0327858 | Livello: Livello 1
225975 | Livello 1 | Piperno | 02 | yes | Parasta_Piano Primo 2 | Parasta Liscia_centrale | 0.0944687 | Livello: Livello 1
225976 | Livello 1 | Piperno | 02 | yes | Parasta_Piano Primo 2 | Parasta Liscia_centrale | 0.00100709 | Livello: Livello 1
225977 | Livello 1 | Piperno | 02 | yes | Parasta_Piano Primo 2 | Parasta Liscia_centrale | 0.00100709 | Livello: Livello 1
225978 | Livello 1 | Piperno | 02 | yes | Parasta_Piano Primo 2 | Parasta Liscia_centrale | 0.00100709 | Livello: Livello 1
225979 | Livello 1 | Piperno | 02 | yes | Parasta_Piano Primo 2 | Parasta Liscia_centrale | 0.00100709 | Livello: Livello 1
225980 | Livello 1 | Piperno | 02 | yes | Parasta_Piano Primo 2 | Parasta Liscia_centrale | 0.00100709 | Livello: Livello 1
225981 | Livello 1 | Piperno | 02 | yes | Parasta_Piano Primo 2 | Parasta Liscia_centrale | 0.00100709 | Livello: Livello 1
225982 | Livello 1 | Piperno | 02 | yes | Parasta_Piano Primo 2 | Parasta Liscia_centrale | 0.00100709 | Livello: Livello 1
225983 | Livello 1 | Piperno | 02 | yes | Parasta_Piano Primo 2 | Parasta Liscia_centrale | 0.00100709 | Livello: Livello 1
225984 | Livello 1 | Piperno | 02 | yes | Parasta_Piano Primo 2 | Parasta Liscia_centrale | 0.00100709 | Livello: Livello 1
225985 | Livello 1 | Piperno | 02 | yes | Parasta_Piano Primo 2 | Parasta Liscia_centrale | 0.00100709 | Livello: Livello 1
225986 | Livello 1 | Piperno | 02 | yes | Parasta_Piano Primo 2 | Parasta Liscia_centrale | 0.00100709 | Livello: Livello 1
225987 | Livello 1 | Piperno | 02 | yes | Parasta_Piano Primo 2 | Parasta Liscia_centrale | 0.00100709 | Livello: Livello 1
225988 | Livello 1 | Piperno | 02 | yes | Parasta_Piano Primo 2 | Parasta Liscia_centrale | 0.00100709 | Livello: Livello 1
225989 | Livello 1 | Piperno | 02 | yes | Parasta_Piano Primo 2 | Parasta Liscia_centrale | 0.00100709 | Livello: Livello 1
225990 | Livello 1 | Piperno | 02 | yes | Parasta_Piano Primo 2 | Parasta Liscia_centrale | 0.00100709 | Livello: Livello 1
225991 | Livello 1 | Piperno | 02 | yes | Parasta_Piano Primo 2 | Parasta Liscia_centrale | 0.00100709 | Livello: Livello 1
225992 | Livello 1 | Piperno | 02 | yes | Parasta_Piano Primo 2 | Parasta Liscia_centrale | 0.00100709 | Livello: Livello 1
225993 | Livello 1 | Piperno | 02 | yes | Parasta_Piano Primo 2 | Parasta Liscia_centrale | 0.00100709 | Livello: Livello 1
225994 | Livello 1 | Piperno | 02 | yes | Parasta_Piano Primo 2 | Parasta Liscia_centrale | 0.00100709 | Livello: Livello 1
225995 | Livello 1 | Piperno | 02 | yes | Parasta_Piano Primo 2 | Parasta Liscia_centrale | 0.00100709 | Livello: Livello 1
225996 | Livello 1 | Piperno | 02 | yes | Parasta_Piano Primo 2 | Parasta Liscia_centrale | 0.0556768 | Livello: Livello 1
225997 | Livello 1 | Piperno | 02 | yes | Parasta_Piano Primo 2 | Parasta Liscia_centrale | 2.15049 | Livello: Livello 1
225998 | Livello 1 |  | 02 | yes | Parasta_Piano Primo 2 | Parasta Liscia_centrale | 0.00594878 | Livello: Livello 1
229239 | Livello 1 | Piperno | 02 | yes | Parasta_Piano Primo 2 | Parasta Liscia_centrale | 0.0423479 | Livello: Livello 1
229240 | Livello 1 | Piperno | 02 | yes | Parasta_Piano Primo 2 | Parasta Liscia_centrale | 0.00427694 | Livello: Livello 1
229241 | Livello 1 | Piperno | 02 | yes | Parasta_Piano Primo 2 | Parasta Liscia_centrale | 0.0423479 | Livello: Livello 1
229242 | Livello 1 | Piperno | 02 | yes | Parasta_Piano Primo 2 | Parasta Liscia_centrale | 0.00427694 | Livello: Livello 1
235061 | Livello 1 | Piperno | 02 | yes | Parasta_ Piano Primo | Parasta Liscia_laterale | 0.173421 | Livello: Livello 1
235062 | Livello 1 | Piperno | 02 | yes | Parasta_ Piano Primo | Parasta Liscia_laterale | 0.0625004 | Livello: Livello 1
235063 | Livello 1 | Piperno | 02 | yes | Parasta_ Piano Primo | Parasta Liscia_laterale | 0.002813 | Livello: Livello 1
235064 | Livello 1 |  | 02 | yes | Parasta_ Piano Primo | Parasta Liscia_laterale | 0.00746349 | Livello: Livello 1
235065 | Livello 1 |  | 02 | yes | Parasta_ Piano Primo | Parasta Liscia_laterale | 0.0176679 | Livello: Livello 1
235066 | Livello 1 | Travertino | 02 | yes | Parasta_ Piano Primo | Parasta Liscia_laterale | 0.101618 | Livello: Livello 1
235067 | Livello 1 | Piperno | 02 | yes | Parasta_ Piano Primo | Parasta Liscia_laterale | 0.653767 | Livello: Livello 1
235068 | Livello 1 | Piperno | 02 | yes | Parasta_ Piano Primo | Parasta Liscia_laterale | 0.0556768 | Livello: Livello 1
235069 | Livello 1 | Piperno | 02 | yes | Parasta_ Piano Primo | Parasta Liscia_laterale | 2.15049 | Livello: Livello 1
235070 | Livello 1 |  | 02 | yes | Parasta_ Piano Primo | Parasta Liscia_laterale | 0.00746349 | Livello: Livello 1
235071 | Livello 1 |  | 02 | yes | Parasta_ Piano Primo | Parasta Liscia_laterale | 0.0176679 | Livello: Livello 1
235072 | Livello 1 | Travertino | 02 | yes | Parasta_ Piano Primo | Parasta Liscia_laterale | 0.101618 | Livello: Livello 1
235073 | Livello 1 | Travertino | 02 | yes | Parasta_ Piano Primo | Parasta Liscia_laterale | 0.066141 | Livello: Livello 1
235074 | Livello 1 | Travertino | 02 | yes | Parasta_ Piano Primo | Parasta Liscia_laterale | 0.108814 | Livello: Livello 1
235075 | Livello 1 | Travertino | 02 | yes | Parasta_ Piano Primo | Parasta Liscia_laterale | 0.0661334 | Livello: Livello 1
235076 | Livello 1 | Travertino | 02 | yes | Parasta_ Piano Primo | Parasta Liscia_laterale | 0.108807 | Livello: Livello 1
235077 | Livello 1 |  | 02 | yes | Parasta_ Piano Primo | Parasta Liscia_laterale | 0.00594878 | Livello: Livello 1
235078 | Livello 1 |  | 02 | yes | Parasta_ Piano Primo | Parasta Liscia_laterale | 0.00807559 | Livello: Livello 1
235079 | Livello 1 |  | 02 | yes | Parasta_ Piano Primo | Parasta Liscia_laterale | 0.0108989 | Livello: Livello 1
235080 | Livello 1 |  | 02 | yes | Parasta_ Piano Primo | Parasta Liscia_laterale | 0.0119519 | Livello: Livello 1
235081 | Livello 1 |  | 02 | yes | Parasta_ Piano Primo | Parasta Liscia_laterale | 0.0161303 | Livello: Livello 1
235082 | Livello 1 | Piperno | 02 | yes | Parasta_ Piano Primo | Parasta Liscia_laterale | 0.189326 | Livello: Livello 1
235083 | Livello 1 | Piperno | 02 | yes | Parasta_ Piano Primo | Parasta Liscia_laterale | 0.0100946 | Livello: Livello 1
235084 | Livello 1 | Piperno | 02 | yes | Parasta_ Piano Primo | Parasta Liscia_laterale | 0.0100946 | Livello: Livello 1
235085 | Livello 1 | Travertino | 02 | yes | Parasta_ Piano Primo | Parasta Liscia_laterale | 0.369222 | Livello: Livello 1
235086 | Livello 1 | Piperno | 02 | yes | Parasta_ Piano Primo | Parasta Liscia_laterale | 0.017309 | Livello: Livello 1
235087 | Livello 1 | Piperno | 02 | yes | Parasta_ Piano Primo | Parasta Liscia_laterale | 0.00282252 | Livello: Livello 1
235088 | Livello 1 | Piperno | 02 | yes | Parasta_ Piano Primo | Parasta Liscia_laterale | 0.0891707 | Livello: Livello 1
235089 | Livello 1 | Piperno | 02 | yes | Parasta_ Piano Primo | Parasta Liscia_laterale | 0.235123 | Livello: Livello 1
235090 | Livello 1 | Piperno | 02 | yes | Parasta_ Piano Primo | Parasta Liscia_laterale | 0.0898849 | Livello: Livello 1
235091 | Livello 1 | Piperno | 02 | yes | Parasta_ Piano Primo | Parasta Liscia_laterale | 0.0327858 | Livello: Livello 1
235092 | Livello 1 | Piperno | 02 | yes | Parasta_ Piano Primo | Parasta Liscia_laterale | 0.0944687 | Livello: Livello 1
235093 | Livello 1 | Piperno | 02 | yes | Parasta_ Piano Primo | Parasta Liscia_laterale | 0.00100709 | Livello: Livello 1
235094 | Livello 1 | Piperno | 02 | yes | Parasta_ Piano Primo | Parasta Liscia_laterale | 0.00100709 | Livello: Livello 1
235095 | Livello 1 | Piperno | 02 | yes | Parasta_ Piano Primo | Parasta Liscia_laterale | 0.00100709 | Livello: Livello 1
235096 | Livello 1 | Piperno | 02 | yes | Parasta_ Piano Primo | Parasta Liscia_laterale | 0.00100709 | Livello: Livello 1
235097 | Livello 1 | Piperno | 02 | yes | Parasta_ Piano Primo | Parasta Liscia_laterale | 0.00100709 | Livello: Livello 1
235098 | Livello 1 | Piperno | 02 | yes | Parasta_ Piano Primo | Parasta Liscia_laterale | 0.00100709 | Livello: Livello 1
235099 | Livello 1 | Piperno | 02 | yes | Parasta_ Piano Primo | Parasta Liscia_laterale | 0.00100709 | Livello: Livello 1
235100 | Livello 1 | Piperno | 02 | yes | Parasta_ Piano Primo | Parasta Liscia_laterale | 0.00100709 | Livello: Livello 1
235101 | Livello 1 | Piperno | 02 | yes | Parasta_ Piano Primo | Parasta Liscia_laterale | 0.00100709 | Livello: Livello 1
235102 | Livello 1 | Piperno | 02 | yes | Parasta_ Piano Primo | Parasta Liscia_laterale | 0.00100709 | Livello: Livello 1
235103 | Livello 1 | Piperno | 02 | yes | Parasta_ Piano Primo | Parasta Liscia_laterale | 0.00100709 | Livello: Livello 1
235104 | Livello 1 | Piperno | 02 | yes | Parasta_ Piano Primo | Parasta Liscia_laterale | 0.00100709 | Livello: Livello 1
235105 | Livello 1 | Piperno | 02 | yes | Parasta_ Piano Primo | Parasta Liscia_laterale | 0.00100709 | Livello: Livello 1
235106 | Livello 1 | Piperno | 02 | yes | Parasta_ Piano Primo | Parasta Liscia_laterale | 0.00100709 | Livello: Livello 1
235107 | Livello 1 | Piperno | 02 | yes | Parasta_ Piano Primo | Parasta Liscia_laterale | 0.00100709 | Livello: Livello 1
235108 | Livello 1 | Piperno | 02 | yes | Parasta_ Piano Primo | Parasta Liscia_laterale | 0.00100709 | Livello: Livello 1
235109 | Livello 1 | Piperno | 02 | yes | Parasta_ Piano Primo | Parasta Liscia_laterale | 0.00100709 | Livello: Livello 1
235110 | Livello 1 | Piperno | 02 | yes | Parasta_ Piano Primo | Parasta Liscia_laterale | 0.00100709 | Livello: Livello 1
235111 | Livello 1 | Piperno | 02 | yes | Parasta_ Piano Primo | Parasta Liscia_laterale | 0.00100709 | Livello: Livello 1
235112 | Livello 1 | Piperno | 02 | yes | Parasta_ Piano Primo | Parasta Liscia_laterale | 0.00100709 | Livello: Livello 1
235113 | Livello 1 | Piperno | 02 | yes | Parasta_ Piano Primo | Parasta Liscia_laterale | 0.0556768 | Livello: Livello 1
235114 | Livello 1 | Piperno | 02 | yes | Parasta_ Piano Primo | Parasta Liscia_laterale | 2.15049 | Livello: Livello 1
235115 | Livello 1 |  | 02 | yes | Parasta_ Piano Primo | Parasta Liscia_laterale | 0.00594878 | Livello: Livello 1
235116 | Livello 1 | Piperno | 02 | yes | Parasta_ Piano Primo | Parasta Liscia_laterale | 0.0423479 | Livello: Livello 1
235117 | Livello 1 | Piperno | 02 | yes | Parasta_ Piano Primo | Parasta Liscia_laterale | 0.00427694 | Livello: Livello 1
235141 | Livello 1 | Piperno | 02 | yes | Parasta_ Piano Primo | Parasta Liscia_laterale | 0.173421 | Livello: Livello 1
235142 | Livello 1 | Piperno | 02 | yes | Parasta_ Piano Primo | Parasta Liscia_laterale | 0.0625004 | Livello: Livello 1
235143 | Livello 1 | Piperno | 02 | yes | Parasta_ Piano Primo | Parasta Liscia_laterale | 0.002813 | Livello: Livello 1
235144 | Livello 1 |  | 02 | yes | Parasta_ Piano Primo | Parasta Liscia_laterale | 0.00746349 | Livello: Livello 1
235145 | Livello 1 |  | 02 | yes | Parasta_ Piano Primo | Parasta Liscia_laterale | 0.0176679 | Livello: Livello 1
235146 | Livello 1 | Travertino | 02 | yes | Parasta_ Piano Primo | Parasta Liscia_laterale | 0.101618 | Livello: Livello 1
235147 | Livello 1 | Piperno | 02 | yes | Parasta_ Piano Primo | Parasta Liscia_laterale | 0.653767 | Livello: Livello 1
235148 | Livello 1 | Piperno | 02 | yes | Parasta_ Piano Primo | Parasta Liscia_laterale | 0.0556768 | Livello: Livello 1
235149 | Livello 1 | Piperno | 02 | yes | Parasta_ Piano Primo | Parasta Liscia_laterale | 2.15049 | Livello: Livello 1
235150 | Livello 1 |  | 02 | yes | Parasta_ Piano Primo | Parasta Liscia_laterale | 0.00746349 | Livello: Livello 1
235151 | Livello 1 |  | 02 | yes | Parasta_ Piano Primo | Parasta Liscia_laterale | 0.0176679 | Livello: Livello 1
235152 | Livello 1 | Travertino | 02 | yes | Parasta_ Piano Primo | Parasta Liscia_laterale | 0.101618 | Livello: Livello 1
235153 | Livello 1 | Travertino | 02 | yes | Parasta_ Piano Primo | Parasta Liscia_laterale | 0.066141 | Livello: Livello 1
235154 | Livello 1 | Travertino | 02 | yes | Parasta_ Piano Primo | Parasta Liscia_laterale | 0.108814 | Livello: Livello 1
235155 | Livello 1 | Travertino | 02 | yes | Parasta_ Piano Primo | Parasta Liscia_laterale | 0.0661334 | Livello: Livello 1
235156 | Livello 1 | Travertino | 02 | yes | Parasta_ Piano Primo | Parasta Liscia_laterale | 0.108807 | Livello: Livello 1
235157 | Livello 1 |  | 02 | yes | Parasta_ Piano Primo | Parasta Liscia_laterale | 0.00594878 | Livello: Livello 1
235158 | Livello 1 |  | 02 | yes | Parasta_ Piano Primo | Parasta Liscia_laterale | 0.00807559 | Livello: Livello 1
235159 | Livello 1 |  | 02 | yes | Parasta_ Piano Primo | Parasta Liscia_laterale | 0.0108989 | Livello: Livello 1
235160 | Livello 1 |  | 02 | yes | Parasta_ Piano Primo | Parasta Liscia_laterale | 0.0119519 | Livello: Livello 1
235161 | Livello 1 |  | 02 | yes | Parasta_ Piano Primo | Parasta Liscia_laterale | 0.0161303 | Livello: Livello 1
235162 | Livello 1 | Piperno | 02 | yes | Parasta_ Piano Primo | Parasta Liscia_laterale | 0.189326 | Livello: Livello 1
235163 | Livello 1 | Piperno | 02 | yes | Parasta_ Piano Primo | Parasta Liscia_laterale | 0.0100946 | Livello: Livello 1
235164 | Livello 1 | Piperno | 02 | yes | Parasta_ Piano Primo | Parasta Liscia_laterale | 0.0100946 | Livello: Livello 1
235165 | Livello 1 | Travertino | 02 | yes | Parasta_ Piano Primo | Parasta Liscia_laterale | 0.369222 | Livello: Livello 1
235166 | Livello 1 | Piperno | 02 | yes | Parasta_ Piano Primo | Parasta Liscia_laterale | 0.017309 | Livello: Livello 1
235167 | Livello 1 | Piperno | 02 | yes | Parasta_ Piano Primo | Parasta Liscia_laterale | 0.00282252 | Livello: Livello 1
235168 | Livello 1 | Piperno | 02 | yes | Parasta_ Piano Primo | Parasta Liscia_laterale | 0.0891707 | Livello: Livello 1
235169 | Livello 1 | Piperno | 02 | yes | Parasta_ Piano Primo | Parasta Liscia_laterale | 0.235123 | Livello: Livello 1
235170 | Livello 1 | Piperno | 02 | yes | Parasta_ Piano Primo | Parasta Liscia_laterale | 0.0898849 | Livello: Livello 1
235171 | Livello 1 | Piperno | 02 | yes | Parasta_ Piano Primo | Parasta Liscia_laterale | 0.0327858 | Livello: Livello 1
235172 | Livello 1 | Piperno | 02 | yes | Parasta_ Piano Primo | Parasta Liscia_laterale | 0.0944687 | Livello: Livello 1
235173 | Livello 1 | Piperno | 02 | yes | Parasta_ Piano Primo | Parasta Liscia_laterale | 0.00100709 | Livello: Livello 1
235174 | Livello 1 | Piperno | 02 | yes | Parasta_ Piano Primo | Parasta Liscia_laterale | 0.00100709 | Livello: Livello 1
235175 | Livello 1 | Piperno | 02 | yes | Parasta_ Piano Primo | Parasta Liscia_laterale | 0.00100709 | Livello: Livello 1
235176 | Livello 1 | Piperno | 02 | yes | Parasta_ Piano Primo | Parasta Liscia_laterale | 0.00100709 | Livello: Livello 1
235177 | Livello 1 | Piperno | 02 | yes | Parasta_ Piano Primo | Parasta Liscia_laterale | 0.00100709 | Livello: Livello 1
235178 | Livello 1 | Piperno | 02 | yes | Parasta_ Piano Primo | Parasta Liscia_laterale | 0.00100709 | Livello: Livello 1
235179 | Livello 1 | Piperno | 02 | yes | Parasta_ Piano Primo | Parasta Liscia_laterale | 0.00100709 | Livello: Livello 1
235180 | Livello 1 | Piperno | 02 | yes | Parasta_ Piano Primo | Parasta Liscia_laterale | 0.00100709 | Livello: Livello 1
235181 | Livello 1 | Piperno | 02 | yes | Parasta_ Piano Primo | Parasta Liscia_laterale | 0.00100709 | Livello: Livello 1
235182 | Livello 1 | Piperno | 02 | yes | Parasta_ Piano Primo | Parasta Liscia_laterale | 0.00100709 | Livello: Livello 1
235183 | Livello 1 | Piperno | 02 | yes | Parasta_ Piano Primo | Parasta Liscia_laterale | 0.00100709 | Livello: Livello 1
235184 | Livello 1 | Piperno | 02 | yes | Parasta_ Piano Primo | Parasta Liscia_laterale | 0.00100709 | Livello: Livello 1
235185 | Livello 1 | Piperno | 02 | yes | Parasta_ Piano Primo | Parasta Liscia_laterale | 0.00100709 | Livello: Livello 1
235186 | Livello 1 | Piperno | 02 | yes | Parasta_ Piano Primo | Parasta Liscia_laterale | 0.00100709 | Livello: Livello 1
235187 | Livello 1 | Piperno | 02 | yes | Parasta_ Piano Primo | Parasta Liscia_laterale | 0.00100709 | Livello: Livello 1
235188 | Livello 1 | Piperno | 02 | yes | Parasta_ Piano Primo | Parasta Liscia_laterale | 0.00100709 | Livello: Livello 1
235189 | Livello 1 | Piperno | 02 | yes | Parasta_ Piano Primo | Parasta Liscia_laterale | 0.00100709 | Livello: Livello 1
235190 | Livello 1 | Piperno | 02 | yes | Parasta_ Piano Primo | Parasta Liscia_laterale | 0.00100709 | Livello: Livello 1
235191 | Livello 1 | Piperno | 02 | yes | Parasta_ Piano Primo | Parasta Liscia_laterale | 0.00100709 | Livello: Livello 1
235192 | Livello 1 | Piperno | 02 | yes | Parasta_ Piano Primo | Parasta Liscia_laterale | 0.00100709 | Livello: Livello 1
235193 | Livello 1 | Piperno | 02 | yes | Parasta_ Piano Primo | Parasta Liscia_laterale | 0.0556768 | Livello: Livello 1
235194 | Livello 1 | Piperno | 02 | yes | Parasta_ Piano Primo | Parasta Liscia_laterale | 2.15049 | Livello: Livello 1
235195 | Livello 1 |  | 02 | yes | Parasta_ Piano Primo | Parasta Liscia_laterale | 0.00594878 | Livello: Livello 1
235196 | Livello 1 | Piperno | 02 | yes | Parasta_ Piano Primo | Parasta Liscia_laterale | 0.0423479 | Livello: Livello 1
235197 | Livello 1 | Piperno | 02 | yes | Parasta_ Piano Primo | Parasta Liscia_laterale | 0.00427694 | Livello: Livello 1

# IfcBuildingElementProxy: Balaustri_balaustra primo livello (37)
In: Livello 2
Type - Material: Travertino
Type - Altro - Categoria: Modelli generici; Nome famiglia: Balaustri_balaustra primo livello
Type - Dati identità - Nome del tipo: Balaustri_balaustra primo livello
Pset_BuildingElementProxyCommon - Reference: Balaustri_balaustra primo livello:Balaustri_balaustra primo livello
Altro - Famiglia: Balaustri_balaustra primo livello: Balaustri_balaustra primo livello; Famiglia e tipo: Balaustri_balaustra primo livello: Balaustri_balaustra primo livello; ID tipo: Balaustri_balaustra primo livello: Balaustri_balaustra primo livello; Tipo: Balaustri_balaustra primo livello: Balaustri_balaustra primo livello
Dati - ESE_AR: 01; ESE_RI: 00; ESE_RI_D: 01; ESE_RI_M: 01
Dimensioni - Area: 0.743236 m2; Volume: 0.0360469 m3
Fasi - Fase di creazione: Fase 1
Vincoli - Sposta con l'oggetto più vicino: no; Host: Livello : Livello 2; Livello: Livello: Livello 2; Offset: 0.24 m
Name (Balaustri_balaustra primo livello:Balaustri_balaustra primo livello:...)
173164
173188
173189
173190
173191
173192
173193
173194
173195
173196
173197
173198
173199
173200
173201
173202
173203
173204
173205
173206
173207
173208
173209
173210
173211
173212
173213
173214
173215
173216
173217
173218
173219
173220
173221
173222
173223

# IfcBuildingElementProxy: Balaustri_balaustra terrazzo (24)
In: Livello 1
Type - Material: Travertino
Type - Altro - Categoria: Modelli generici; Nome famiglia: Balaustri_balaustra terrazzo
Type - Dati identità - Nome del tipo: Balaustri_balaustra terrazzo
Pset_BuildingElementProxyCommon - Reference: Balaustri_balaustra terrazzo:Balaustri_balaustra terrazzo
Altro - Famiglia: Balaustri_balaustra terrazzo: Balaustri_balaustra terrazzo; Famiglia e tipo: Balaustri_balaustra terrazzo: Balaustri_balaustra terrazzo; ID tipo: Balaustri_balaustra terrazzo: Balaustri_balaustra terrazzo; Tipo: Balaustri_balaustra terrazzo: Balaustri_balaustra terrazzo
Dati - ESE_AR: 02; ESE_RI: 00; ESE_RI_D: 02; ESE_RI_M: 02
Dimensioni - Area: 0.366455 m2; Volume: 0.0135839 m3
Fasi - Fase di creazione: Fase 1
Vincoli - Sposta con l'oggetto più vicino: no; Livello: Livello: Livello 1; Host: Livello : Livello 1
Name (Balaustri_balaustra terrazzo:Balaustri_balaustra terrazzo:...) | Offset (m)
179298 | -9.18159
179299 | -9.18159
179300 | -9.18159
179301 | -9.18159
179302 | -9.18159
179303 | -9.18159
179304 | -9.18159
179305 | -9.18159
179306 | -9.18159
179307 | -9.18159
179308 | -9.18159
179309 | -9.18159
179310 | -9.16659
179311 | -9.16659
179312 | -9.16659
179313 | -9.16659
179314 | -9.16659
179315 | -9.16659
179316 | -9.16659
179317 | -9.16659
179318 | -9.16659
179319 | -9.16659
179320 | -9.16659
179321 | -9.16659

# IfcBuildingElementProxy: Cimasa_balaustra primo livello_2, Cimasa_balaustra primo livello_2:Cimasa_balaustra primo livello_2:175998
In: Livello 2
Type - Material: Piperno
Type - Altro - Categoria: Modelli generici; Nome famiglia: Cimasa_balaustra primo livello_2
Type - Dati identità - Nome del tipo: Cimasa_balaustra primo livello_2
Pset_BuildingElementProxyCommon - Reference: Cimasa_balaustra primo livello_2:Cimasa_balaustra primo livello_2
Altro - Famiglia: Cimasa_balaustra primo livello_2: Cimasa_balaustra primo livello_2; Famiglia e tipo: Cimasa_balaustra primo livello_2: Cimasa_balaustra primo livello_2; ID tipo: Cimasa_balaustra primo livello_2: Cimasa_balaustra primo livello_2; Tipo: Cimasa_balaustra primo livello_2: Cimasa_balaustra primo livello_2
Dati - ESE_AR: 01; ESE_RI: 00; ESE_RI_D: 01; ESE_RI_M: 01
Dimensioni - Area: 0.130362 m2; Volume: 0.474666 m3
Fasi - Fase di creazione: Fase 1
Vincoli - Sposta con l'oggetto più vicino: no

# IfcBuildingElementProxy: Cimasa_balaustra primo livello_3, Cimasa_balaustra primo livello_3:Cimasa_balaustra primo livello_3:175283
In: Livello 2
Type - Material: Piperno
Type - Altro - Categoria: Modelli generici; Nome famiglia: Cimasa_balaustra primo livello_3
Type - Dati identità - Nome del tipo: Cimasa_balaustra primo livello_3
Pset_BuildingElementProxyCommon - Reference: Cimasa_balaustra primo livello_3:Cimasa_balaustra primo livello_3
Altro - Famiglia: Cimasa_balaustra primo livello_3: Cimasa_balaustra primo livello_3; Famiglia e tipo: Cimasa_balaustra primo livello_3: Cimasa_balaustra primo livello_3; ID tipo: Cimasa_balaustra primo livello_3: Cimasa_balaustra primo livello_3; Tipo: Cimasa_balaustra primo livello_3: Cimasa_balaustra primo livello_3
Dati - ESE_AR: 01; ESE_RI: 00; ESE_RI_D: 01; ESE_RI_M: 01
Dimensioni - Area: 0.136827 m2; Volume: 0.379136 m3
Fasi - Fase di creazione: Fase 1
Vincoli - Sposta con l'oggetto più vicino: no; Prospetto: 0 m

# IfcBuildingElementProxy: Cimasa_balaustra primo livello_3, Cimasa_balaustra primo livello_4:Cimasa_balaustra primo livello_3:203282
In: Livello 2
Type - Material: Piperno
Type - Altro - Categoria: Modelli generici; Nome famiglia: Cimasa_balaustra primo livello_4
Type - Dati identità - Nome del tipo: Cimasa_balaustra primo livello_3
Pset_BuildingElementProxyCommon - Reference: Cimasa_balaustra primo livello_4:Cimasa_balaustra primo livello_3
Altro - Famiglia: Cimasa_balaustra primo livello_4: Cimasa_balaustra primo livello_3; Famiglia e tipo: Cimasa_balaustra primo livello_4: Cimasa_balaustra primo livello_3; ID tipo: Cimasa_balaustra primo livello_4: Cimasa_balaustra primo livello_3; Tipo: Cimasa_balaustra primo livello_4: Cimasa_balaustra primo livello_3
Dati - ESE_AR: 01; ESE_RI: 00; ESE_RI_D: 01; ESE_RI_M: 01
Dimensioni - Area: 0.137062 m2; Volume: 0.380232 m3
Fasi - Fase di creazione: Fase 1
Vincoli - Sposta con l'oggetto più vicino: no; Prospetto: 0 m

# IfcBuildingElementProxy: Cimasa_balaustra terrazzo_1, Cimasa_balaustra terrazzo_1:Cimasa_balaustra terrazzo_1:195837
In: Livello 3
Type - Material: Piperno
Type - Altro - Categoria: Modelli generici; Nome famiglia: Cimasa_balaustra terrazzo_1
Type - Dati identità - Nome del tipo: Cimasa_balaustra terrazzo_1
Pset_BuildingElementProxyCommon - Reference: Cimasa_balaustra terrazzo_1:Cimasa_balaustra terrazzo_1
Altro - Famiglia: Cimasa_balaustra terrazzo_1: Cimasa_balaustra terrazzo_1; Famiglia e tipo: Cimasa_balaustra terrazzo_1: Cimasa_balaustra terrazzo_1; ID tipo: Cimasa_balaustra terrazzo_1: Cimasa_balaustra terrazzo_1; Tipo: Cimasa_balaustra terrazzo_1: Cimasa_balaustra terrazzo_1
Dati - ESE_AR: 02; ESE_RI: 00; ESE_RI_D: 02; ESE_RI_M: 02
Dimensioni - Area: 0.212795 m2; Volume: 0.497359 m3
Fasi - Fase di creazione: Fase 1
Vincoli - Sposta con l'oggetto più vicino: no; Prospetto: 0 m

# IfcBuildingElementProxy: Cimasa_balaustra terrazzo_2, Cimasa_balaustra terrazzo_2:Cimasa_balaustra terrazzo_2:180913
In: Livello 3
Type - Material: Piperno
Type - Altro - Categoria: Modelli generici; Nome famiglia: Cimasa_balaustra terrazzo_2
Type - Dati identità - Nome del tipo: Cimasa_balaustra terrazzo_2
Pset_BuildingElementProxyCommon - Reference: Cimasa_balaustra terrazzo_2:Cimasa_balaustra terrazzo_2
Altro - Famiglia: Cimasa_balaustra terrazzo_2: Cimasa_balaustra terrazzo_2; Famiglia e tipo: Cimasa_balaustra terrazzo_2: Cimasa_balaustra terrazzo_2; ID tipo: Cimasa_balaustra terrazzo_2: Cimasa_balaustra terrazzo_2; Tipo: Cimasa_balaustra terrazzo_2: Cimasa_balaustra terrazzo_2
Dati - ESE_AR: 02; ESE_RI: 00; ESE_RI_D: 02; ESE_RI_M: 02
Dimensioni - Area: 0.194744 m2; Volume: 0.367452 m3
Fasi - Fase di creazione: Fase 1
Vincoli - Sposta con l'oggetto più vicino: no; Prospetto: 0 m
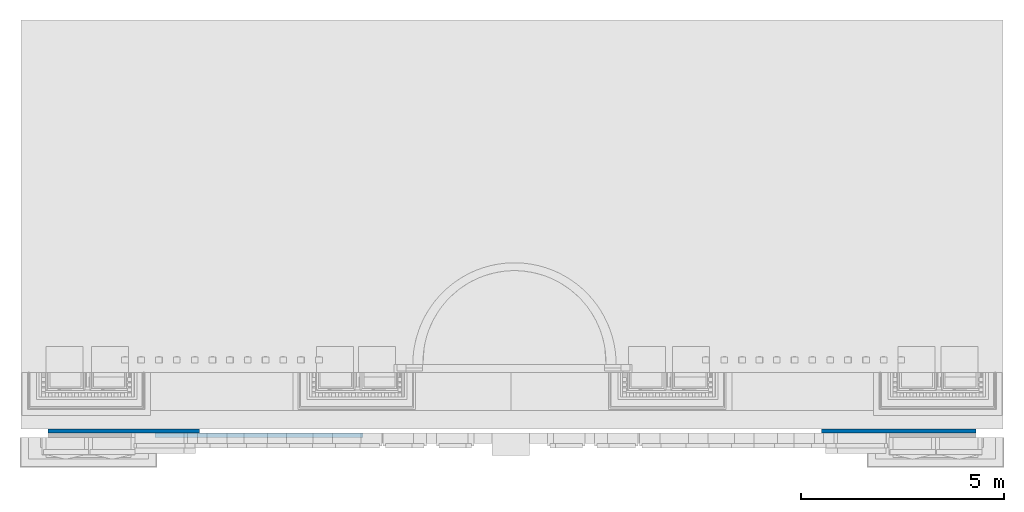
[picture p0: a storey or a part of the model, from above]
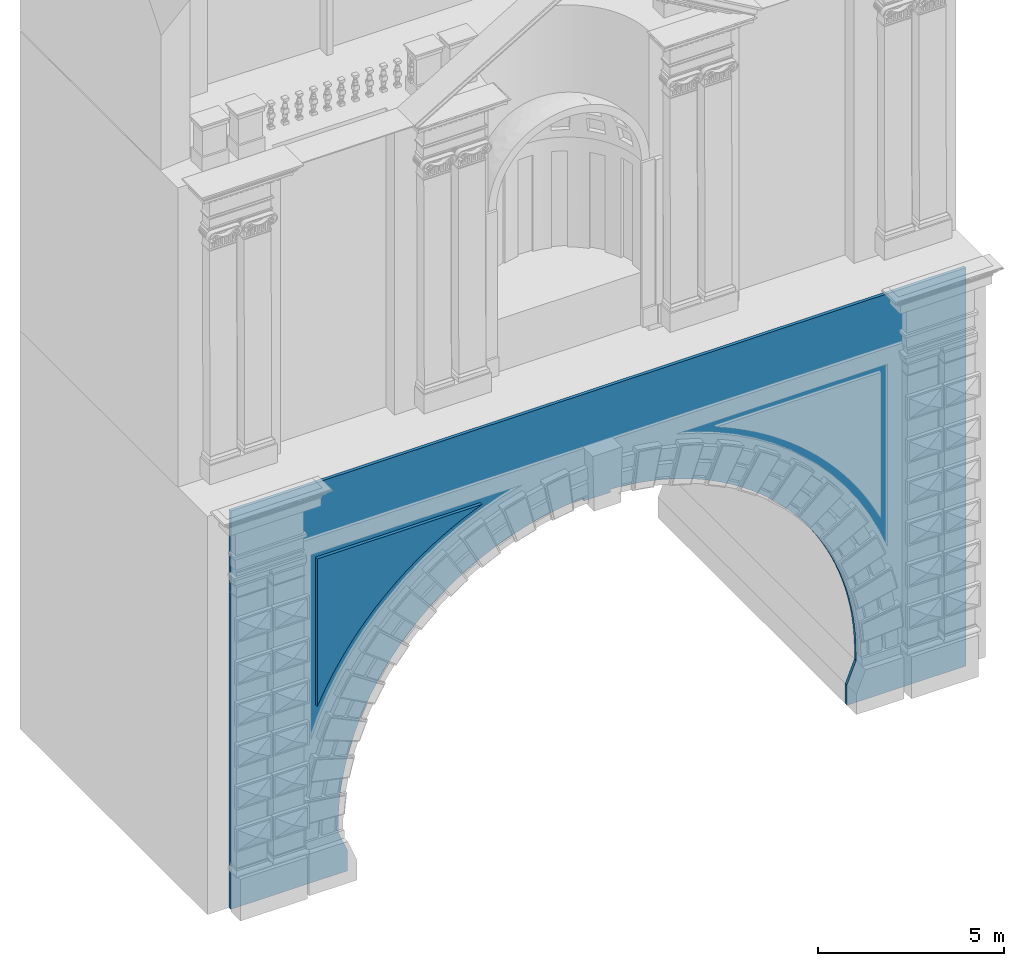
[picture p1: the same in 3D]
Properties of the parts of a building model (IFC2X3), part 2 of 2

# IfcBuildingElementProxy: Cornice Frontone, Cornice Frontone:Cornice Frontone:176662
In: Livello 1
Type - Material: Piperno
Type - Altro - Categoria: Modelli generici; Nome famiglia: Cornice Frontone
Type - Dati identità - Nome del tipo: Cornice Frontone
Pset_BuildingElementProxyCommon - Reference: Cornice Frontone:Cornice Frontone
Altro - Famiglia: Cornice Frontone: Cornice Frontone; Famiglia e tipo: Cornice Frontone: Cornice Frontone; ID tipo: Cornice Frontone: Cornice Frontone; Tipo: Cornice Frontone: Cornice Frontone
Dati - ESE_AR: 02; ESE_RI: 00; ESE_RI_D: 02; ESE_RI_M: 02
Dimensioni - Area: 70.5911 m2; Volume: 2.93855 m3
Fasi - Fase di creazione: Fase 1
Vincoli - Sposta con l'oggetto più vicino: no; Host: Livello : Livello 1; Livello: Livello: Livello 1; Offset: -9.17918 m

# IfcBuildingElementProxy: Cornice coronamento_1, Cornice coronamento_1:Cornice coronamento_1:176091
In: Livello 2
Type - Material: Piperno, Travertino
Type - Altro - Categoria: Modelli generici; Nome famiglia: Cornice coronamento_1
Type - Dati identità - Nome del tipo: Cornice coronamento_1
Pset_BuildingElementProxyCommon - Reference: Cornice coronamento_1:Cornice coronamento_1
Altro - Famiglia: Cornice coronamento_1: Cornice coronamento_1; Famiglia e tipo: Cornice coronamento_1: Cornice coronamento_1; ID tipo: Cornice coronamento_1: Cornice coronamento_1; Tipo: Cornice coronamento_1: Cornice coronamento_1
Dati - ESE_AR: 02; ESE_RI: 00; ESE_RI_D: 02; ESE_RI_M: 02
Dimensioni - Area: 0.339419 m2; Volume: 1.61944 m3
Fasi - Fase di creazione: Fase 1
Vincoli - Sposta con l'oggetto più vicino: no

# IfcBuildingElementProxy: Cornice_nicchia centrale, Cornice_nicchia centrale:Cornice_nicchia centrale:176661
In: Livello 3
Type - Material: Piperno, Travertino
Type - Altro - Categoria: Modelli generici; Nome famiglia: Cornice_nicchia centrale
Type - Dati identità - Nome del tipo: Cornice_nicchia centrale
Pset_BuildingElementProxyCommon - Reference: Cornice_nicchia centrale:Cornice_nicchia centrale
Altro - Famiglia: Cornice_nicchia centrale: Cornice_nicchia centrale; Famiglia e tipo: Cornice_nicchia centrale: Cornice_nicchia centrale; ID tipo: Cornice_nicchia centrale: Cornice_nicchia centrale; Tipo: Cornice_nicchia centrale: Cornice_nicchia centrale
Dati - ESE_AR: 02; ESE_RI: 00; ESE_RI_D: 02; ESE_RI_M: 02
Dimensioni - Area: 14.114 m2; Volume: 0.944687 m3
Fasi - Fase di creazione: Fase 1
Vincoli - Sposta con l'oggetto più vicino: no; Host: Livello : Livello 3; Livello: Livello: Livello 3; Offset: -4.60467 m

# IfcBuildingElementProxy: Cornicione_Fronte Arcoleo, Cornicione_Fronte Arcoleo:Cornicione_Fronte Arcoleo:144348
In: Livello 2
Type - Material: Piperno, Travertino
Type - Altro - Categoria: Modelli generici; Nome famiglia: Cornicione_Fronte Arcoleo
Type - Dati identità - Nome del tipo: Cornicione_Fronte Arcoleo
Pset_BuildingElementProxyCommon - Reference: Cornicione_Fronte Arcoleo:Cornicione_Fronte Arcoleo
Altro - Famiglia: Cornicione_Fronte Arcoleo: Cornicione_Fronte Arcoleo; Famiglia e tipo: Cornicione_Fronte Arcoleo: Cornicione_Fronte Arcoleo; ID tipo: Cornicione_Fronte Arcoleo: Cornicione_Fronte Arcoleo; Tipo: Cornicione_Fronte Arcoleo: Cornicione_Fronte Arcoleo
Dati - ESE_AR: 01; ESE_RI: 00; ESE_RI_D: 01; ESE_RI_M: 01
Dimensioni - Area: 72.54 m2; Volume: 9.75521 m3
Fasi - Fase di creazione: Fase 1
Vincoli - Host: Livello : Livello 2; Livello: Livello: Livello 2; Offset: -2.01245 m; Sposta con l'oggetto più vicino: no

# IfcBuildingElementProxy: Dentelli, Dentelli Cornice:Dentelli:176139
In: Livello 2
Type - Material: Piperno
Type - Altro - Categoria: Modelli generici; Nome famiglia: Dentelli Cornice
Type - Dati identità - Nome del tipo: Dentelli
Pset_BuildingElementProxyCommon - Reference: Dentelli Cornice:Dentelli
Altro - Famiglia: Dentelli Cornice: Dentelli; Famiglia e tipo: Dentelli Cornice: Dentelli; ID tipo: Dentelli Cornice: Dentelli; Tipo: Dentelli Cornice: Dentelli
Dimensioni - Area: 0.697957 m2; Volume: 0.0373138 m3
Fasi - Fase di creazione: Fase 1
Vincoli - Sposta con l'oggetto più vicino: no; Prospetto: 0 m

# IfcBuildingElementProxy: Estrusione galleria, Galleria:Estrusione galleria:221638
In: Livello 1
Type - Altro - Categoria: Contesto; Nome famiglia: Galleria
Type - Dati identità - Nome del tipo: Estrusione galleria
Type - Dimensioni - Altezza: 0 m
Pset_BuildingElementProxyCommon - Reference: Galleria:Estrusione galleria
Altro - Famiglia: Galleria: Estrusione galleria; Famiglia e tipo: Galleria: Estrusione galleria; ID tipo: Galleria: Estrusione galleria; Tipo: Galleria: Estrusione galleria
Dimensioni - Area: 188.473 m2; Volume: 1896.16 m3
Fasi - Fase di creazione: Fase 1
Vincoli - Sposta con l'oggetto più vicino: no

# IfcBuildingElementProxy: Galleria_2, Galleria_2:Galleria_2:222592
In: Livello 1
Type - Altro - Categoria: Contesto; Nome famiglia: Galleria_2
Type - Dati identità - Nome del tipo: Galleria_2
Type - Dimensioni - Altezza: 0 m
Pset_BuildingElementProxyCommon - Reference: Galleria_2:Galleria_2
Altro - Famiglia: Galleria_2: Galleria_2; Famiglia e tipo: Galleria_2: Galleria_2; ID tipo: Galleria_2: Galleria_2; Tipo: Galleria_2: Galleria_2
Dimensioni - Area: 308.621 m2; Volume: 2887.02 m3
Fasi - Fase di creazione: Fase 1
Vincoli - Sposta con l'oggetto più vicino: no

# IfcBuildingElementProxy: Piedistallo_balaustra primo livello (8)
In: Livello 2
Type - Material: Piperno
Type - Altro - Categoria: Modelli generici; Nome famiglia: Piedistallo_balaustra primo livello
Type - Dati identità - Nome del tipo: Piedistallo_balaustra primo livello
Pset_BuildingElementProxyCommon - Reference: Piedistallo_balaustra primo livello:Piedistallo_balaustra primo livello
Altro - Famiglia: Piedistallo_balaustra primo livello: Piedistallo_balaustra primo livello; Famiglia e tipo: Piedistallo_balaustra primo livello: Piedistallo_balaustra primo livello; ID tipo: Piedistallo_balaustra primo livello: Piedistallo_balaustra primo livello; Tipo: Piedistallo_balaustra primo livello: Piedistallo_balaustra primo livello
Dati - ESE_AR: 01; ESE_RI: 00; ESE_RI_D: 01; ESE_RI_M: 01
Dimensioni - Area: 3.53935 m2; Volume: 0.467654 m3
Fasi - Fase di creazione: Fase 1
Vincoli - Livello: Livello: Livello 2; Sposta con l'oggetto più vicino: no; Host: Livello : Livello 2; Offset: 0 m
Name (Piedistallo_balaustra primo livello:Piedistallo_balaustra primo livello:...)
173165
173166
173167
173168
173169
173170
173171
173172

# IfcBuildingElementProxy: Piedistallo_balaustra terrazzo (8)
In: Livello 1
Type - Material: Piperno
Type - Altro - Categoria: Modelli generici; Nome famiglia: Piedistallo_balaustra terrazzo
Type - Dati identità - Nome del tipo: Piedistallo_balaustra terrazzo
Pset_BuildingElementProxyCommon - Reference: Piedistallo_balaustra terrazzo:Piedistallo_balaustra terrazzo
Altro - Famiglia: Piedistallo_balaustra terrazzo: Piedistallo_balaustra terrazzo; Famiglia e tipo: Piedistallo_balaustra terrazzo: Piedistallo_balaustra terrazzo; ID tipo: Piedistallo_balaustra terrazzo: Piedistallo_balaustra terrazzo; Tipo: Piedistallo_balaustra terrazzo: Piedistallo_balaustra terrazzo
Dati - ESE_AR: 02; ESE_RI: 00; ESE_RI_D: 02; ESE_RI_M: 02
Fasi - Fase di creazione: Fase 1
Vincoli - Sposta con l'oggetto più vicino: no; Livello: Livello: Livello 1; Host: Livello : Livello 1
Name (Piedistallo_balaustra terrazzo:Piedistallo_balaustra terrazzo:...) | Area (m2) | Volume (m3) | Offset (m)
179290 | 3.76512 | 0.575374 | -9.18168
179291 | 3.76512 | 0.575374 | -9.18168
179292 | 3.76512 | 0.575374 | -9.18168
179293 | 3.76452 | 0.575357 | -9.18168
179294 | 3.76512 | 0.575374 | -9.16168
179295 | 3.76512 | 0.575374 | -9.16168
179296 | 3.76512 | 0.575374 | -9.16168
179297 | 3.76512 | 0.575374 | -9.16168

# IfcBuildingElementProxy: Timpano, Timpano:Timpano:198693
In: Livello 3
Type - Material: Piperno
Type - Altro - Categoria: Modelli generici; Nome famiglia: Timpano
Type - Dati identità - Nome del tipo: Timpano
Pset_BuildingElementProxyCommon - Reference: Timpano:Timpano
Altro - Famiglia: Timpano: Timpano; Famiglia e tipo: Timpano: Timpano; ID tipo: Timpano: Timpano; Tipo: Timpano: Timpano
Dati - ESE_AR: 02; ESE_RI: 00; ESE_RI_D: 02; ESE_RI_M: 02
Dimensioni - Area: 13.0827 m2; Volume: 0.667945 m3
Fasi - Fase di creazione: Fase 1
Vincoli - Sposta con l'oggetto più vicino: no; Host: Livello : Livello 3; Livello: Livello: Livello 3; Offset: -0.738055 m

# IfcRoof: Tetto di base:Generico - 400 mm:1398, Tetto di base:Generico - 400 mm:180507
In: Livello 3
Material: Asfalto, Bitume
Pset_RoofCommon - IsExternal: yes; Reference: Tetto di base:Generico - 400 mm; TotalArea: 45.0297 m2; ProjectedArea: 38.8142 m2
Altro - Categoria: Tetti; Famiglia: Tetto di base: Generico - 400 mm; Famiglia e tipo: Tetto di base: Generico - 400 mm; ID tipo: Tetto di base: Generico - 400 mm; Tipo: Tetto di base: Generico - 400 mm
Costruzione - Profondità fascia: 0 m; Taglio trave: Taglio a piombo
Dati - ESE_AR: 02; ESE_RI: 00; ESE_RI_D: 02; ESE_RI_M: 02
Dimensioni - Area: 45.0297 m2; Spessore: 0.4 m; Volume: 18.0118 m3
Fasi - Fase di creazione: Fase 1
Vincoli - Delimita il locale: yes; Relativo a massa: no; Fine estrusione: -5.39784 m; Inizio estrusione: -1.79784 m; Livello di riferimento: Livello: Livello 3; Offset del livello: 0 m; Piano di lavoro: Muro di base : Generico - 200 mm
Proprietà analitiche(Type) - Ruvidità: 3; Assorbimento: 0.7; Coefficiente di scambio termico (U): 2.875; Massa termica: 782880; Resistenza termica (R): 0.347826
Grafica(Type) - Colore del retino a dettaglio basso: 0
Dati identità(Type) - Nome del tipo: Generico - 400 mm
Costruzione(Type) - Spessore di default: 0.4 m
Altro(Type) - Categoria: Tetti; Nome famiglia: Tetto di base

# IfcRoof: Tetto di base:Terrazzo (2)
Pset_RoofCommon - IsExternal: yes; Reference: Tetto di base:Terrazzo
Altro - Categoria: Tetti; Famiglia: Tetto di base: Terrazzo; Famiglia e tipo: Tetto di base: Terrazzo; ID tipo: Tetto di base: Terrazzo; Tipo: Tetto di base: Terrazzo
Costruzione - Altezza massima del colmo: 23.2894 m; Profondità fascia: 0 m; Taglio trave: Taglio a piombo
Dati - ESE_AR: 02; ESE_RI: 00; ESE_RI_D: 02; ESE_RI_M: 02
Dimensioni - Spessore: 0.4 m
Fasi - Fase di creazione: Fase 1
Vincoli - Delimita il locale: yes; Relativo a massa: no; Offset livello di taglio: 0 m
Altro(Type) - Categoria: Tetti; Nome famiglia: Tetto di base
Costruzione(Type) - Spessore di default: 0.4 m
Dati identità(Type) - Nome del tipo: Terrazzo
Grafica(Type) - Colore del retino a dettaglio basso: 0
Proprietà analitiche(Type) - Ruvidità: 3; Assorbimento: 0.7; Coefficiente di scambio termico (U): 2; Massa termica: 578000; Resistenza termica (R): 0.5
Name (Tetto di base:Terrazzo:...) | In | TotalArea (m2) = ProjectedArea (m2) = Area (m2) | Volume (m3) | Livello di base | Offset della base dal livello (m)
179373 | Livello 3 | 21.703 | 8.68119 | Livello: Livello 3 | -0.44
179998 | Livello 2 | 26.5466 | 10.6186 | Livello: Livello 2 | 9.52258

# IfcSlab: Pavimento:Basamento_Balaustra (3)
In: Livello 2
PredefinedType: FLOOR; Material: Piperno 0.3 m
Pset_SlabCommon - LoadBearing: no; IsExternal: no; Reference: Pavimento:Basamento_Balaustra; ThermalTransmittance: 9.66667 kg/K/s3
Altro - Categoria: Pavimenti; Famiglia: Pavimento: Basamento_Balaustra; Famiglia e tipo: Pavimento: Basamento_Balaustra; ID tipo: Pavimento: Basamento_Balaustra; Tipo: Pavimento: Basamento_Balaustra
Dati - ESE_AR: 01; ESE_RI: 00; ESE_RI_D: 01; ESE_RI_M: 01
Dimensioni - Area: 5.66778 m2; Perimetro: 33.016 m; Quota altimetrica base: 13.3068 m; Quota altimetrica parte superiore: 13.6068 m; Spessore: 0.3 m; Volume: 1.70033 m3
Fasi - Fase di creazione: Fase 1
Strutturale - Attiva modello analitico: no; Strutturale: no
Vincoli - Delimita il locale: yes; Livello: Livello: Livello 2; Offset di altezza da livello: 0.24 m; Relativo a massa: no
Altro(Type) - Categoria: Pavimenti; Nome famiglia: Pavimento
Costruzione(Type) - Funzione: Interno; Spessore di default: 0.3 m
Dati identità(Type) - Nome del tipo: Basamento_Balaustra
Grafica(Type) - Colore del retino a dettaglio basso: 0
Materiali e finiture(Type) - Materiale strutturale: Piperno
Proprietà analitiche(Type) - Assorbimento: 0.7; Coefficiente di scambio termico (U): 9.66667; Massa termica: 693000; Resistenza termica (R): 0.103448; Ruvidità: 3
Name (Pavimento:Basamento_Balaustra:...) | GrossArea (m2) | Perimeter (m)
173175 | 1.80258 | 10.3227
173175:2 | 2.02308 | 12.3909
173175:3 | 1.84212 | 10.3024

# IfcSlab: Pavimento:Basamento_Balaustra 2 (2)
In: Livello 3
PredefinedType: FLOOR; Material: Piperno 0.45 m
Proprietà analitiche(Type) - Ruvidità: 3; Assorbimento: 0.7; Coefficiente di scambio termico (U): 6.44444; Massa termica: 1039500; Resistenza termica (R): 0.155172
Materiali e finiture(Type) - Materiale strutturale: Piperno
Grafica(Type) - Colore del retino a dettaglio basso: 0
Dati identità(Type) - Nome del tipo: Basamento_Balaustra 2
Costruzione(Type) - Funzione: Interno; Spessore di default: 0.45 m
Altro(Type) - Categoria: Pavimenti; Nome famiglia: Pavimento
Pset_SlabCommon - LoadBearing: no; IsExternal: no; Reference: Pavimento:Basamento_Balaustra 2; ThermalTransmittance: 6.44444 kg/K/s3
Altro - Categoria: Pavimenti; Famiglia: Pavimento: Basamento_Balaustra 2; Famiglia e tipo: Pavimento: Basamento_Balaustra 2; ID tipo: Pavimento: Basamento_Balaustra 2; Tipo: Pavimento: Basamento_Balaustra 2
Dati - ESE_AR: 02; ESE_RI: 00; ESE_RI_D: 02; ESE_RI_M: 02
Dimensioni - Area: 3.6447 m2; Perimetro: 20.6251 m; Quota altimetrica base: 23.2894 m; Quota altimetrica parte superiore: 23.7394 m; Spessore: 0.45 m; Volume: 1.64011 m3
Fasi - Fase di creazione: Fase 1
Strutturale - Attiva modello analitico: no; Strutturale: no
Vincoli - Delimita il locale: yes; Relativo a massa: no; Livello: Livello: Livello 3; Offset di altezza da livello: 0.41 m
Name (Pavimento:Basamento_Balaustra 2:...) | GrossArea (m2) | Perimeter (m)
195964 | 1.80258 | 10.3227
195964:2 | 1.84212 | 10.3024

# IfcSlab: Pavimento:Pavimento terrazzo primo livello, Pavimento:Pavimento terrazzo primo livello:173532
In: Livello 2
PredefinedType: FLOOR; Material: Battuto di cemento 0.3 m
Pset_SlabCommon - LoadBearing: no; IsExternal: no; Reference: Pavimento:Pavimento terrazzo primo livello; PitchAngle: 0 deg
BaseQuantities - GrossArea: 50.5136 m2; GrossVolume: 15.1541 m3; Perimeter: 54.6297 m; Width: 0.3 m
Altro - Categoria: Pavimenti; Famiglia: Pavimento: Pavimento terrazzo primo livello; Famiglia e tipo: Pavimento: Pavimento terrazzo primo livello; ID tipo: Pavimento: Pavimento terrazzo primo livello; Tipo: Pavimento: Pavimento terrazzo primo livello
Dimensioni - Area: 50.5136 m2; Perimetro: 54.6297 m; Quota altimetrica base: 13.0668 m; Quota altimetrica parte superiore: 13.3668 m; Spessore: 0.3 m; Volume: 15.1538 m3
Fasi - Fase di creazione: Fase 1
Strutturale - Attiva modello analitico: no; Strutturale: no
Vincoli - Delimita il locale: yes; Livello: Livello: Livello 2; Relativo a massa: no; Offset di altezza da livello: 0 m
Altro(Type) - Categoria: Pavimenti; Nome famiglia: Pavimento
Costruzione(Type) - Funzione: Interno; Spessore di default: 0.3 m
Dati identità(Type) - Nome del tipo: Pavimento terrazzo primo livello
Grafica(Type) - Colore del retino a dettaglio basso: 0
Materiali e finiture(Type) - Materiale strutturale: Battuto di cemento
Proprietà analitiche(Type) - Ruvidità: 3; Assorbimento: 0.7

# IfcSlab: Tetto di base:Terrazzo (2)
PredefinedType: ROOF; Material: Piastrella, Quadrello 0.4 m
Pset_SlabCommon - PitchAngle: 0 deg; IsExternal: yes; Reference: Tetto di base:Terrazzo; ThermalTransmittance: 2 kg/K/s3
BaseQuantities - Width: 0.4 m
Name (Tetto di base:Terrazzo:...) | In | GrossArea (m2) | GrossVolume (m3) | Perimeter (m)
179373 | Livello 3 | 2.01627 | 0.806509 | 20.6326
179998 | Livello 2 | 2.46626 | 0.986503 | 21.774

# IfcWall (4)
In: Livello 1
Material: Travertino
Pset_WallCommon - Reference: Stratigrafia; LoadBearing: no; ExtendToStructure: no; IsExternal: no
Altro - Categoria: Stratigrafia
Dati identità - Categoria originale: Muri; Costruzione: Nucleo; Famiglia originale: Muro di base; Materiale: Travertino; Tipo originale: Generico - 200 mm
Dimensioni - Esclusione: no; Spessore: 0.1 m
Fasi - Fase creata da originale: yes; Fase demolita da originale: yes; Fase di creazione: Fase 1
Vincoli - Livello di base: Livello: Livello 1
Name (Stratigrafia:...) | Materiale in base a originale = Mostra punti di manipolazione = La forma è stata modificata | Altezza (m) | Area (m2) | Lunghezza (m) | Volume (m3) | ESE_AR = ESE_RI_D = ESE_RI_M | ESE_RI
141900 | yes | 13.0668 | 171.063 | 22.8114 | 17.1063
142087 | no | 11.3668 | 106.147 | 22.8114 | 10.6147 | 01 | 00
142176 | no | 4.84238 | 9.21733 | 5.11131 | 0.921733 | 01 | 00
142177 | no | 4.7898 | 9.17458 | 5.11708 | 0.917458 | 01 | 00

# IfcWall: Muro di base:Generico - 200 mm, Muro di base:Generico - 200 mm:176034
In: Livello 2
Type - Material: Travertino 0.1 m, Travertino 0.1 m
Type - Altro - Categoria: Muri; Nome famiglia: Muro di base
Type - Costruzione - Funzione: Esterno; Larghezza: 0.2 m; Ripiegatura agli inserti: Non ripiegare; Ripiegatura alle estremità: Nessuno
Type - Dati identità - Nome del tipo: Generico - 200 mm
Type - Grafica - Colore del retino a dettaglio basso: 0
Type - Materiali e finiture - Materiale strutturale: Travertino
Type - Proprietà analitiche - Ruvidità: 3; Assorbimento: 0.7; Coefficiente di scambio termico (U): 14.5; Massa termica: 462000; Resistenza termica (R): 0.0689655
Material: Travertino (2)
Altro - Famiglia: Muro di base: Generico - 200 mm; Famiglia e tipo: Muro di base: Generico - 200 mm; ID tipo: Muro di base: Generico - 200 mm; Tipo: Muro di base: Generico - 200 mm
Dati - ESE_AR: 02; ESE_RI: 00; ESE_RI_D: 02; ESE_RI_M: 02
Dimensioni - Area: 187.016 m2; Lunghezza: 24.0759 m; Volume: 37.403 m3
Fasi - Fase di creazione: Fase 1
Strutturale - Attiva modello analitico: no; Strutturale: no; Utilizzo strutturale: Non portante
Vincoli - Delimita il locale: yes; Relativo a massa: no; Altezza non collegata: 13.4109 m; Distanza estensione base: 0 m; Distanza estensione superiore: 0 m; La base è associata: no; La parte superiore è associata: no; Linea di ubicazione: Superficie di finitura: esterno; Offset base: 0 m; Offset superiore: 0 m; Vincolo di base: Livello: Livello 2
Pset_WallCommon - LoadBearing: no; ExtendToStructure: no; Reference: Muro di base:Generico - 200 mm; IsExternal: yes; ThermalTransmittance: 14.5 kg/K/s3
